# Generated by FakeRAM 2.0
VERSION 5.7 ;
BUSBITCHARS "[]" ;
PROPERTYDEFINITIONS
  MACRO width INTEGER ;
  MACRO depth INTEGER ;
  MACRO banks INTEGER ;
END PROPERTYDEFINITIONS
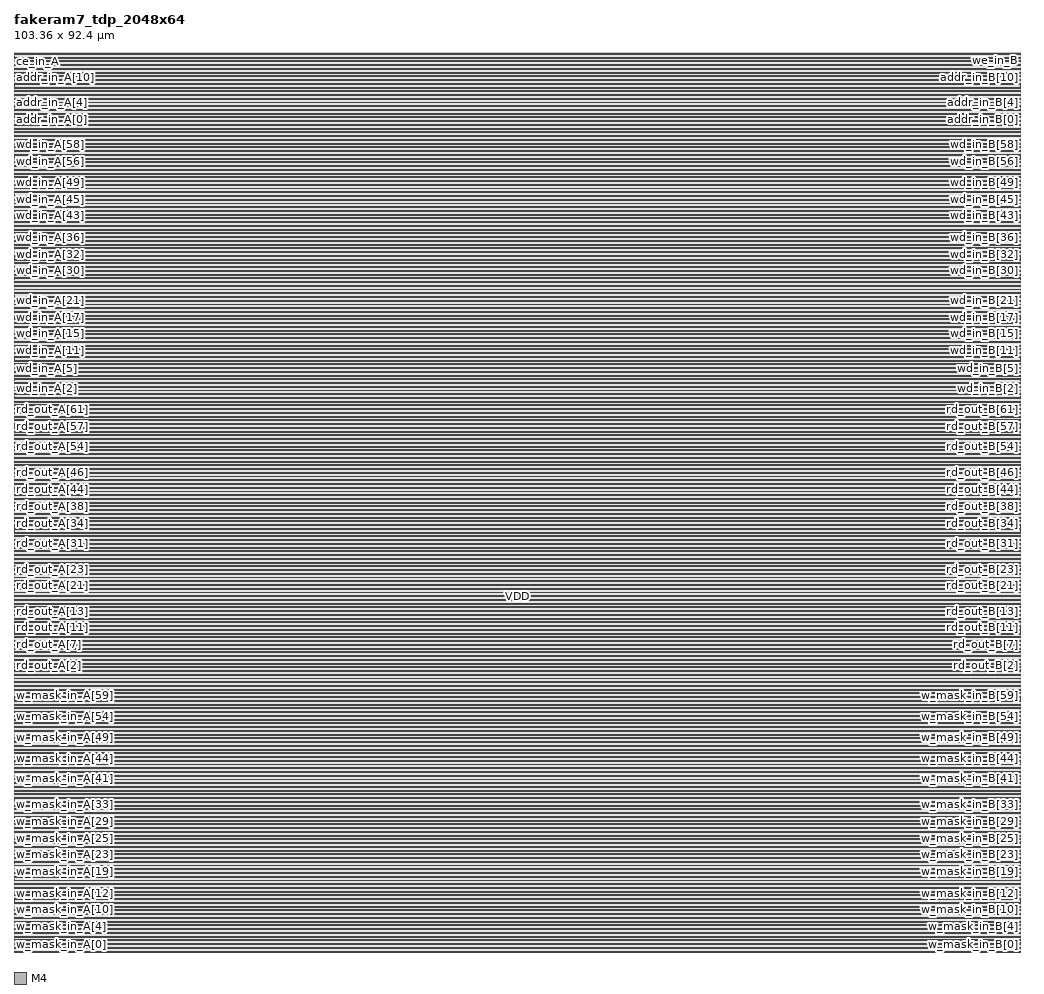
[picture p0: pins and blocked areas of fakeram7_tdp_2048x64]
MACRO fakeram7_tdp_2048x64
  PROPERTY width 64 ;
  PROPERTY depth 2048 ;
  PROPERTY banks 8 ;
  FOREIGN fakeram7_tdp_2048x64 0 0 ;
  SYMMETRY X Y ;
  SIZE 103.360 BY 92.400 ;
  CLASS BLOCK ;
  PIN w_mask_in_A[0]
    DIRECTION INPUT ;
    USE SIGNAL ;
    SHAPE ABUTMENT ;
    PORT
      LAYER M4 ;
      RECT 0.000 0.048 0.024 0.072 ;
    END
  END w_mask_in_A[0]
  PIN w_mask_in_B[0]
    DIRECTION INPUT ;
    USE SIGNAL ;
    SHAPE ABUTMENT ;
    PORT
      LAYER M4 ;
      RECT 103.336 0.048 103.360 0.072 ;
    END
  END w_mask_in_B[0]
  PIN w_mask_in_A[1]
    DIRECTION INPUT ;
    USE SIGNAL ;
    SHAPE ABUTMENT ;
    PORT
      LAYER M4 ;
      RECT 0.000 0.480 0.024 0.504 ;
    END
  END w_mask_in_A[1]
  PIN w_mask_in_B[1]
    DIRECTION INPUT ;
    USE SIGNAL ;
    SHAPE ABUTMENT ;
    PORT
      LAYER M4 ;
      RECT 103.336 0.480 103.360 0.504 ;
    END
  END w_mask_in_B[1]
  PIN w_mask_in_A[2]
    DIRECTION INPUT ;
    USE SIGNAL ;
    SHAPE ABUTMENT ;
    PORT
      LAYER M4 ;
      RECT 0.000 0.912 0.024 0.936 ;
    END
  END w_mask_in_A[2]
  PIN w_mask_in_B[2]
    DIRECTION INPUT ;
    USE SIGNAL ;
    SHAPE ABUTMENT ;
    PORT
      LAYER M4 ;
      RECT 103.336 0.912 103.360 0.936 ;
    END
  END w_mask_in_B[2]
  PIN w_mask_in_A[3]
    DIRECTION INPUT ;
    USE SIGNAL ;
    SHAPE ABUTMENT ;
    PORT
      LAYER M4 ;
      RECT 0.000 1.344 0.024 1.368 ;
    END
  END w_mask_in_A[3]
  PIN w_mask_in_B[3]
    DIRECTION INPUT ;
    USE SIGNAL ;
    SHAPE ABUTMENT ;
    PORT
      LAYER M4 ;
      RECT 103.336 1.344 103.360 1.368 ;
    END
  END w_mask_in_B[3]
  PIN w_mask_in_A[4]
    DIRECTION INPUT ;
    USE SIGNAL ;
    SHAPE ABUTMENT ;
    PORT
      LAYER M4 ;
      RECT 0.000 1.776 0.024 1.800 ;
    END
  END w_mask_in_A[4]
  PIN w_mask_in_B[4]
    DIRECTION INPUT ;
    USE SIGNAL ;
    SHAPE ABUTMENT ;
    PORT
      LAYER M4 ;
      RECT 103.336 1.776 103.360 1.800 ;
    END
  END w_mask_in_B[4]
  PIN w_mask_in_A[5]
    DIRECTION INPUT ;
    USE SIGNAL ;
    SHAPE ABUTMENT ;
    PORT
      LAYER M4 ;
      RECT 0.000 2.208 0.024 2.232 ;
    END
  END w_mask_in_A[5]
  PIN w_mask_in_B[5]
    DIRECTION INPUT ;
    USE SIGNAL ;
    SHAPE ABUTMENT ;
    PORT
      LAYER M4 ;
      RECT 103.336 2.208 103.360 2.232 ;
    END
  END w_mask_in_B[5]
  PIN w_mask_in_A[6]
    DIRECTION INPUT ;
    USE SIGNAL ;
    SHAPE ABUTMENT ;
    PORT
      LAYER M4 ;
      RECT 0.000 2.640 0.024 2.664 ;
    END
  END w_mask_in_A[6]
  PIN w_mask_in_B[6]
    DIRECTION INPUT ;
    USE SIGNAL ;
    SHAPE ABUTMENT ;
    PORT
      LAYER M4 ;
      RECT 103.336 2.640 103.360 2.664 ;
    END
  END w_mask_in_B[6]
  PIN w_mask_in_A[7]
    DIRECTION INPUT ;
    USE SIGNAL ;
    SHAPE ABUTMENT ;
    PORT
      LAYER M4 ;
      RECT 0.000 3.072 0.024 3.096 ;
    END
  END w_mask_in_A[7]
  PIN w_mask_in_B[7]
    DIRECTION INPUT ;
    USE SIGNAL ;
    SHAPE ABUTMENT ;
    PORT
      LAYER M4 ;
      RECT 103.336 3.072 103.360 3.096 ;
    END
  END w_mask_in_B[7]
  PIN w_mask_in_A[8]
    DIRECTION INPUT ;
    USE SIGNAL ;
    SHAPE ABUTMENT ;
    PORT
      LAYER M4 ;
      RECT 0.000 3.504 0.024 3.528 ;
    END
  END w_mask_in_A[8]
  PIN w_mask_in_B[8]
    DIRECTION INPUT ;
    USE SIGNAL ;
    SHAPE ABUTMENT ;
    PORT
      LAYER M4 ;
      RECT 103.336 3.504 103.360 3.528 ;
    END
  END w_mask_in_B[8]
  PIN w_mask_in_A[9]
    DIRECTION INPUT ;
    USE SIGNAL ;
    SHAPE ABUTMENT ;
    PORT
      LAYER M4 ;
      RECT 0.000 3.936 0.024 3.960 ;
    END
  END w_mask_in_A[9]
  PIN w_mask_in_B[9]
    DIRECTION INPUT ;
    USE SIGNAL ;
    SHAPE ABUTMENT ;
    PORT
      LAYER M4 ;
      RECT 103.336 3.936 103.360 3.960 ;
    END
  END w_mask_in_B[9]
  PIN w_mask_in_A[10]
    DIRECTION INPUT ;
    USE SIGNAL ;
    SHAPE ABUTMENT ;
    PORT
      LAYER M4 ;
      RECT 0.000 4.368 0.024 4.392 ;
    END
  END w_mask_in_A[10]
  PIN w_mask_in_B[10]
    DIRECTION INPUT ;
    USE SIGNAL ;
    SHAPE ABUTMENT ;
    PORT
      LAYER M4 ;
      RECT 103.336 4.368 103.360 4.392 ;
    END
  END w_mask_in_B[10]
  PIN w_mask_in_A[11]
    DIRECTION INPUT ;
    USE SIGNAL ;
    SHAPE ABUTMENT ;
    PORT
      LAYER M4 ;
      RECT 0.000 4.800 0.024 4.824 ;
    END
  END w_mask_in_A[11]
  PIN w_mask_in_B[11]
    DIRECTION INPUT ;
    USE SIGNAL ;
    SHAPE ABUTMENT ;
    PORT
      LAYER M4 ;
      RECT 103.336 4.800 103.360 4.824 ;
    END
  END w_mask_in_B[11]
  PIN w_mask_in_A[12]
    DIRECTION INPUT ;
    USE SIGNAL ;
    SHAPE ABUTMENT ;
    PORT
      LAYER M4 ;
      RECT 0.000 5.232 0.024 5.256 ;
    END
  END w_mask_in_A[12]
  PIN w_mask_in_B[12]
    DIRECTION INPUT ;
    USE SIGNAL ;
    SHAPE ABUTMENT ;
    PORT
      LAYER M4 ;
      RECT 103.336 5.232 103.360 5.256 ;
    END
  END w_mask_in_B[12]
  PIN w_mask_in_A[13]
    DIRECTION INPUT ;
    USE SIGNAL ;
    SHAPE ABUTMENT ;
    PORT
      LAYER M4 ;
      RECT 0.000 5.664 0.024 5.688 ;
    END
  END w_mask_in_A[13]
  PIN w_mask_in_B[13]
    DIRECTION INPUT ;
    USE SIGNAL ;
    SHAPE ABUTMENT ;
    PORT
      LAYER M4 ;
      RECT 103.336 5.664 103.360 5.688 ;
    END
  END w_mask_in_B[13]
  PIN w_mask_in_A[14]
    DIRECTION INPUT ;
    USE SIGNAL ;
    SHAPE ABUTMENT ;
    PORT
      LAYER M4 ;
      RECT 0.000 6.096 0.024 6.120 ;
    END
  END w_mask_in_A[14]
  PIN w_mask_in_B[14]
    DIRECTION INPUT ;
    USE SIGNAL ;
    SHAPE ABUTMENT ;
    PORT
      LAYER M4 ;
      RECT 103.336 6.096 103.360 6.120 ;
    END
  END w_mask_in_B[14]
  PIN w_mask_in_A[15]
    DIRECTION INPUT ;
    USE SIGNAL ;
    SHAPE ABUTMENT ;
    PORT
      LAYER M4 ;
      RECT 0.000 6.528 0.024 6.552 ;
    END
  END w_mask_in_A[15]
  PIN w_mask_in_B[15]
    DIRECTION INPUT ;
    USE SIGNAL ;
    SHAPE ABUTMENT ;
    PORT
      LAYER M4 ;
      RECT 103.336 6.528 103.360 6.552 ;
    END
  END w_mask_in_B[15]
  PIN w_mask_in_A[16]
    DIRECTION INPUT ;
    USE SIGNAL ;
    SHAPE ABUTMENT ;
    PORT
      LAYER M4 ;
      RECT 0.000 6.960 0.024 6.984 ;
    END
  END w_mask_in_A[16]
  PIN w_mask_in_B[16]
    DIRECTION INPUT ;
    USE SIGNAL ;
    SHAPE ABUTMENT ;
    PORT
      LAYER M4 ;
      RECT 103.336 6.960 103.360 6.984 ;
    END
  END w_mask_in_B[16]
  PIN w_mask_in_A[17]
    DIRECTION INPUT ;
    USE SIGNAL ;
    SHAPE ABUTMENT ;
    PORT
      LAYER M4 ;
      RECT 0.000 7.392 0.024 7.416 ;
    END
  END w_mask_in_A[17]
  PIN w_mask_in_B[17]
    DIRECTION INPUT ;
    USE SIGNAL ;
    SHAPE ABUTMENT ;
    PORT
      LAYER M4 ;
      RECT 103.336 7.392 103.360 7.416 ;
    END
  END w_mask_in_B[17]
  PIN w_mask_in_A[18]
    DIRECTION INPUT ;
    USE SIGNAL ;
    SHAPE ABUTMENT ;
    PORT
      LAYER M4 ;
      RECT 0.000 7.824 0.024 7.848 ;
    END
  END w_mask_in_A[18]
  PIN w_mask_in_B[18]
    DIRECTION INPUT ;
    USE SIGNAL ;
    SHAPE ABUTMENT ;
    PORT
      LAYER M4 ;
      RECT 103.336 7.824 103.360 7.848 ;
    END
  END w_mask_in_B[18]
  PIN w_mask_in_A[19]
    DIRECTION INPUT ;
    USE SIGNAL ;
    SHAPE ABUTMENT ;
    PORT
      LAYER M4 ;
      RECT 0.000 8.256 0.024 8.280 ;
    END
  END w_mask_in_A[19]
  PIN w_mask_in_B[19]
    DIRECTION INPUT ;
    USE SIGNAL ;
    SHAPE ABUTMENT ;
    PORT
      LAYER M4 ;
      RECT 103.336 8.256 103.360 8.280 ;
    END
  END w_mask_in_B[19]
  PIN w_mask_in_A[20]
    DIRECTION INPUT ;
    USE SIGNAL ;
    SHAPE ABUTMENT ;
    PORT
      LAYER M4 ;
      RECT 0.000 8.688 0.024 8.712 ;
    END
  END w_mask_in_A[20]
  PIN w_mask_in_B[20]
    DIRECTION INPUT ;
    USE SIGNAL ;
    SHAPE ABUTMENT ;
    PORT
      LAYER M4 ;
      RECT 103.336 8.688 103.360 8.712 ;
    END
  END w_mask_in_B[20]
  PIN w_mask_in_A[21]
    DIRECTION INPUT ;
    USE SIGNAL ;
    SHAPE ABUTMENT ;
    PORT
      LAYER M4 ;
      RECT 0.000 9.120 0.024 9.144 ;
    END
  END w_mask_in_A[21]
  PIN w_mask_in_B[21]
    DIRECTION INPUT ;
    USE SIGNAL ;
    SHAPE ABUTMENT ;
    PORT
      LAYER M4 ;
      RECT 103.336 9.120 103.360 9.144 ;
    END
  END w_mask_in_B[21]
  PIN w_mask_in_A[22]
    DIRECTION INPUT ;
    USE SIGNAL ;
    SHAPE ABUTMENT ;
    PORT
      LAYER M4 ;
      RECT 0.000 9.552 0.024 9.576 ;
    END
  END w_mask_in_A[22]
  PIN w_mask_in_B[22]
    DIRECTION INPUT ;
    USE SIGNAL ;
    SHAPE ABUTMENT ;
    PORT
      LAYER M4 ;
      RECT 103.336 9.552 103.360 9.576 ;
    END
  END w_mask_in_B[22]
  PIN w_mask_in_A[23]
    DIRECTION INPUT ;
    USE SIGNAL ;
    SHAPE ABUTMENT ;
    PORT
      LAYER M4 ;
      RECT 0.000 9.984 0.024 10.008 ;
    END
  END w_mask_in_A[23]
  PIN w_mask_in_B[23]
    DIRECTION INPUT ;
    USE SIGNAL ;
    SHAPE ABUTMENT ;
    PORT
      LAYER M4 ;
      RECT 103.336 9.984 103.360 10.008 ;
    END
  END w_mask_in_B[23]
  PIN w_mask_in_A[24]
    DIRECTION INPUT ;
    USE SIGNAL ;
    SHAPE ABUTMENT ;
    PORT
      LAYER M4 ;
      RECT 0.000 10.416 0.024 10.440 ;
    END
  END w_mask_in_A[24]
  PIN w_mask_in_B[24]
    DIRECTION INPUT ;
    USE SIGNAL ;
    SHAPE ABUTMENT ;
    PORT
      LAYER M4 ;
      RECT 103.336 10.416 103.360 10.440 ;
    END
  END w_mask_in_B[24]
  PIN w_mask_in_A[25]
    DIRECTION INPUT ;
    USE SIGNAL ;
    SHAPE ABUTMENT ;
    PORT
      LAYER M4 ;
      RECT 0.000 10.848 0.024 10.872 ;
    END
  END w_mask_in_A[25]
  PIN w_mask_in_B[25]
    DIRECTION INPUT ;
    USE SIGNAL ;
    SHAPE ABUTMENT ;
    PORT
      LAYER M4 ;
      RECT 103.336 10.848 103.360 10.872 ;
    END
  END w_mask_in_B[25]
  PIN w_mask_in_A[26]
    DIRECTION INPUT ;
    USE SIGNAL ;
    SHAPE ABUTMENT ;
    PORT
      LAYER M4 ;
      RECT 0.000 11.280 0.024 11.304 ;
    END
  END w_mask_in_A[26]
  PIN w_mask_in_B[26]
    DIRECTION INPUT ;
    USE SIGNAL ;
    SHAPE ABUTMENT ;
    PORT
      LAYER M4 ;
      RECT 103.336 11.280 103.360 11.304 ;
    END
  END w_mask_in_B[26]
  PIN w_mask_in_A[27]
    DIRECTION INPUT ;
    USE SIGNAL ;
    SHAPE ABUTMENT ;
    PORT
      LAYER M4 ;
      RECT 0.000 11.712 0.024 11.736 ;
    END
  END w_mask_in_A[27]
  PIN w_mask_in_B[27]
    DIRECTION INPUT ;
    USE SIGNAL ;
    SHAPE ABUTMENT ;
    PORT
      LAYER M4 ;
      RECT 103.336 11.712 103.360 11.736 ;
    END
  END w_mask_in_B[27]
  PIN w_mask_in_A[28]
    DIRECTION INPUT ;
    USE SIGNAL ;
    SHAPE ABUTMENT ;
    PORT
      LAYER M4 ;
      RECT 0.000 12.144 0.024 12.168 ;
    END
  END w_mask_in_A[28]
  PIN w_mask_in_B[28]
    DIRECTION INPUT ;
    USE SIGNAL ;
    SHAPE ABUTMENT ;
    PORT
      LAYER M4 ;
      RECT 103.336 12.144 103.360 12.168 ;
    END
  END w_mask_in_B[28]
  PIN w_mask_in_A[29]
    DIRECTION INPUT ;
    USE SIGNAL ;
    SHAPE ABUTMENT ;
    PORT
      LAYER M4 ;
      RECT 0.000 12.576 0.024 12.600 ;
    END
  END w_mask_in_A[29]
  PIN w_mask_in_B[29]
    DIRECTION INPUT ;
    USE SIGNAL ;
    SHAPE ABUTMENT ;
    PORT
      LAYER M4 ;
      RECT 103.336 12.576 103.360 12.600 ;
    END
  END w_mask_in_B[29]
  PIN w_mask_in_A[30]
    DIRECTION INPUT ;
    USE SIGNAL ;
    SHAPE ABUTMENT ;
    PORT
      LAYER M4 ;
      RECT 0.000 13.008 0.024 13.032 ;
    END
  END w_mask_in_A[30]
  PIN w_mask_in_B[30]
    DIRECTION INPUT ;
    USE SIGNAL ;
    SHAPE ABUTMENT ;
    PORT
      LAYER M4 ;
      RECT 103.336 13.008 103.360 13.032 ;
    END
  END w_mask_in_B[30]
  PIN w_mask_in_A[31]
    DIRECTION INPUT ;
    USE SIGNAL ;
    SHAPE ABUTMENT ;
    PORT
      LAYER M4 ;
      RECT 0.000 13.440 0.024 13.464 ;
    END
  END w_mask_in_A[31]
  PIN w_mask_in_B[31]
    DIRECTION INPUT ;
    USE SIGNAL ;
    SHAPE ABUTMENT ;
    PORT
      LAYER M4 ;
      RECT 103.336 13.440 103.360 13.464 ;
    END
  END w_mask_in_B[31]
  PIN w_mask_in_A[32]
    DIRECTION INPUT ;
    USE SIGNAL ;
    SHAPE ABUTMENT ;
    PORT
      LAYER M4 ;
      RECT 0.000 13.872 0.024 13.896 ;
    END
  END w_mask_in_A[32]
  PIN w_mask_in_B[32]
    DIRECTION INPUT ;
    USE SIGNAL ;
    SHAPE ABUTMENT ;
    PORT
      LAYER M4 ;
      RECT 103.336 13.872 103.360 13.896 ;
    END
  END w_mask_in_B[32]
  PIN w_mask_in_A[33]
    DIRECTION INPUT ;
    USE SIGNAL ;
    SHAPE ABUTMENT ;
    PORT
      LAYER M4 ;
      RECT 0.000 14.304 0.024 14.328 ;
    END
  END w_mask_in_A[33]
  PIN w_mask_in_B[33]
    DIRECTION INPUT ;
    USE SIGNAL ;
    SHAPE ABUTMENT ;
    PORT
      LAYER M4 ;
      RECT 103.336 14.304 103.360 14.328 ;
    END
  END w_mask_in_B[33]
  PIN w_mask_in_A[34]
    DIRECTION INPUT ;
    USE SIGNAL ;
    SHAPE ABUTMENT ;
    PORT
      LAYER M4 ;
      RECT 0.000 14.736 0.024 14.760 ;
    END
  END w_mask_in_A[34]
  PIN w_mask_in_B[34]
    DIRECTION INPUT ;
    USE SIGNAL ;
    SHAPE ABUTMENT ;
    PORT
      LAYER M4 ;
      RECT 103.336 14.736 103.360 14.760 ;
    END
  END w_mask_in_B[34]
  PIN w_mask_in_A[35]
    DIRECTION INPUT ;
    USE SIGNAL ;
    SHAPE ABUTMENT ;
    PORT
      LAYER M4 ;
      RECT 0.000 15.168 0.024 15.192 ;
    END
  END w_mask_in_A[35]
  PIN w_mask_in_B[35]
    DIRECTION INPUT ;
    USE SIGNAL ;
    SHAPE ABUTMENT ;
    PORT
      LAYER M4 ;
      RECT 103.336 15.168 103.360 15.192 ;
    END
  END w_mask_in_B[35]
  PIN w_mask_in_A[36]
    DIRECTION INPUT ;
    USE SIGNAL ;
    SHAPE ABUTMENT ;
    PORT
      LAYER M4 ;
      RECT 0.000 15.600 0.024 15.624 ;
    END
  END w_mask_in_A[36]
  PIN w_mask_in_B[36]
    DIRECTION INPUT ;
    USE SIGNAL ;
    SHAPE ABUTMENT ;
    PORT
      LAYER M4 ;
      RECT 103.336 15.600 103.360 15.624 ;
    END
  END w_mask_in_B[36]
  PIN w_mask_in_A[37]
    DIRECTION INPUT ;
    USE SIGNAL ;
    SHAPE ABUTMENT ;
    PORT
      LAYER M4 ;
      RECT 0.000 16.032 0.024 16.056 ;
    END
  END w_mask_in_A[37]
  PIN w_mask_in_B[37]
    DIRECTION INPUT ;
    USE SIGNAL ;
    SHAPE ABUTMENT ;
    PORT
      LAYER M4 ;
      RECT 103.336 16.032 103.360 16.056 ;
    END
  END w_mask_in_B[37]
  PIN w_mask_in_A[38]
    DIRECTION INPUT ;
    USE SIGNAL ;
    SHAPE ABUTMENT ;
    PORT
      LAYER M4 ;
      RECT 0.000 16.464 0.024 16.488 ;
    END
  END w_mask_in_A[38]
  PIN w_mask_in_B[38]
    DIRECTION INPUT ;
    USE SIGNAL ;
    SHAPE ABUTMENT ;
    PORT
      LAYER M4 ;
      RECT 103.336 16.464 103.360 16.488 ;
    END
  END w_mask_in_B[38]
  PIN w_mask_in_A[39]
    DIRECTION INPUT ;
    USE SIGNAL ;
    SHAPE ABUTMENT ;
    PORT
      LAYER M4 ;
      RECT 0.000 16.896 0.024 16.920 ;
    END
  END w_mask_in_A[39]
  PIN w_mask_in_B[39]
    DIRECTION INPUT ;
    USE SIGNAL ;
    SHAPE ABUTMENT ;
    PORT
      LAYER M4 ;
      RECT 103.336 16.896 103.360 16.920 ;
    END
  END w_mask_in_B[39]
  PIN w_mask_in_A[40]
    DIRECTION INPUT ;
    USE SIGNAL ;
    SHAPE ABUTMENT ;
    PORT
      LAYER M4 ;
      RECT 0.000 17.328 0.024 17.352 ;
    END
  END w_mask_in_A[40]
  PIN w_mask_in_B[40]
    DIRECTION INPUT ;
    USE SIGNAL ;
    SHAPE ABUTMENT ;
    PORT
      LAYER M4 ;
      RECT 103.336 17.328 103.360 17.352 ;
    END
  END w_mask_in_B[40]
  PIN w_mask_in_A[41]
    DIRECTION INPUT ;
    USE SIGNAL ;
    SHAPE ABUTMENT ;
    PORT
      LAYER M4 ;
      RECT 0.000 17.760 0.024 17.784 ;
    END
  END w_mask_in_A[41]
  PIN w_mask_in_B[41]
    DIRECTION INPUT ;
    USE SIGNAL ;
    SHAPE ABUTMENT ;
    PORT
      LAYER M4 ;
      RECT 103.336 17.760 103.360 17.784 ;
    END
  END w_mask_in_B[41]
  PIN w_mask_in_A[42]
    DIRECTION INPUT ;
    USE SIGNAL ;
    SHAPE ABUTMENT ;
    PORT
      LAYER M4 ;
      RECT 0.000 18.192 0.024 18.216 ;
    END
  END w_mask_in_A[42]
  PIN w_mask_in_B[42]
    DIRECTION INPUT ;
    USE SIGNAL ;
    SHAPE ABUTMENT ;
    PORT
      LAYER M4 ;
      RECT 103.336 18.192 103.360 18.216 ;
    END
  END w_mask_in_B[42]
  PIN w_mask_in_A[43]
    DIRECTION INPUT ;
    USE SIGNAL ;
    SHAPE ABUTMENT ;
    PORT
      LAYER M4 ;
      RECT 0.000 18.624 0.024 18.648 ;
    END
  END w_mask_in_A[43]
  PIN w_mask_in_B[43]
    DIRECTION INPUT ;
    USE SIGNAL ;
    SHAPE ABUTMENT ;
    PORT
      LAYER M4 ;
      RECT 103.336 18.624 103.360 18.648 ;
    END
  END w_mask_in_B[43]
  PIN w_mask_in_A[44]
    DIRECTION INPUT ;
    USE SIGNAL ;
    SHAPE ABUTMENT ;
    PORT
      LAYER M4 ;
      RECT 0.000 19.056 0.024 19.080 ;
    END
  END w_mask_in_A[44]
  PIN w_mask_in_B[44]
    DIRECTION INPUT ;
    USE SIGNAL ;
    SHAPE ABUTMENT ;
    PORT
      LAYER M4 ;
      RECT 103.336 19.056 103.360 19.080 ;
    END
  END w_mask_in_B[44]
  PIN w_mask_in_A[45]
    DIRECTION INPUT ;
    USE SIGNAL ;
    SHAPE ABUTMENT ;
    PORT
      LAYER M4 ;
      RECT 0.000 19.488 0.024 19.512 ;
    END
  END w_mask_in_A[45]
  PIN w_mask_in_B[45]
    DIRECTION INPUT ;
    USE SIGNAL ;
    SHAPE ABUTMENT ;
    PORT
      LAYER M4 ;
      RECT 103.336 19.488 103.360 19.512 ;
    END
  END w_mask_in_B[45]
  PIN w_mask_in_A[46]
    DIRECTION INPUT ;
    USE SIGNAL ;
    SHAPE ABUTMENT ;
    PORT
      LAYER M4 ;
      RECT 0.000 19.920 0.024 19.944 ;
    END
  END w_mask_in_A[46]
  PIN w_mask_in_B[46]
    DIRECTION INPUT ;
    USE SIGNAL ;
    SHAPE ABUTMENT ;
    PORT
      LAYER M4 ;
      RECT 103.336 19.920 103.360 19.944 ;
    END
  END w_mask_in_B[46]
  PIN w_mask_in_A[47]
    DIRECTION INPUT ;
    USE SIGNAL ;
    SHAPE ABUTMENT ;
    PORT
      LAYER M4 ;
      RECT 0.000 20.352 0.024 20.376 ;
    END
  END w_mask_in_A[47]
  PIN w_mask_in_B[47]
    DIRECTION INPUT ;
    USE SIGNAL ;
    SHAPE ABUTMENT ;
    PORT
      LAYER M4 ;
      RECT 103.336 20.352 103.360 20.376 ;
    END
  END w_mask_in_B[47]
  PIN w_mask_in_A[48]
    DIRECTION INPUT ;
    USE SIGNAL ;
    SHAPE ABUTMENT ;
    PORT
      LAYER M4 ;
      RECT 0.000 20.784 0.024 20.808 ;
    END
  END w_mask_in_A[48]
  PIN w_mask_in_B[48]
    DIRECTION INPUT ;
    USE SIGNAL ;
    SHAPE ABUTMENT ;
    PORT
      LAYER M4 ;
      RECT 103.336 20.784 103.360 20.808 ;
    END
  END w_mask_in_B[48]
  PIN w_mask_in_A[49]
    DIRECTION INPUT ;
    USE SIGNAL ;
    SHAPE ABUTMENT ;
    PORT
      LAYER M4 ;
      RECT 0.000 21.216 0.024 21.240 ;
    END
  END w_mask_in_A[49]
  PIN w_mask_in_B[49]
    DIRECTION INPUT ;
    USE SIGNAL ;
    SHAPE ABUTMENT ;
    PORT
      LAYER M4 ;
      RECT 103.336 21.216 103.360 21.240 ;
    END
  END w_mask_in_B[49]
  PIN w_mask_in_A[50]
    DIRECTION INPUT ;
    USE SIGNAL ;
    SHAPE ABUTMENT ;
    PORT
      LAYER M4 ;
      RECT 0.000 21.648 0.024 21.672 ;
    END
  END w_mask_in_A[50]
  PIN w_mask_in_B[50]
    DIRECTION INPUT ;
    USE SIGNAL ;
    SHAPE ABUTMENT ;
    PORT
      LAYER M4 ;
      RECT 103.336 21.648 103.360 21.672 ;
    END
  END w_mask_in_B[50]
  PIN w_mask_in_A[51]
    DIRECTION INPUT ;
    USE SIGNAL ;
    SHAPE ABUTMENT ;
    PORT
      LAYER M4 ;
      RECT 0.000 22.080 0.024 22.104 ;
    END
  END w_mask_in_A[51]
  PIN w_mask_in_B[51]
    DIRECTION INPUT ;
    USE SIGNAL ;
    SHAPE ABUTMENT ;
    PORT
      LAYER M4 ;
      RECT 103.336 22.080 103.360 22.104 ;
    END
  END w_mask_in_B[51]
  PIN w_mask_in_A[52]
    DIRECTION INPUT ;
    USE SIGNAL ;
    SHAPE ABUTMENT ;
    PORT
      LAYER M4 ;
      RECT 0.000 22.512 0.024 22.536 ;
    END
  END w_mask_in_A[52]
  PIN w_mask_in_B[52]
    DIRECTION INPUT ;
    USE SIGNAL ;
    SHAPE ABUTMENT ;
    PORT
      LAYER M4 ;
      RECT 103.336 22.512 103.360 22.536 ;
    END
  END w_mask_in_B[52]
  PIN w_mask_in_A[53]
    DIRECTION INPUT ;
    USE SIGNAL ;
    SHAPE ABUTMENT ;
    PORT
      LAYER M4 ;
      RECT 0.000 22.944 0.024 22.968 ;
    END
  END w_mask_in_A[53]
  PIN w_mask_in_B[53]
    DIRECTION INPUT ;
    USE SIGNAL ;
    SHAPE ABUTMENT ;
    PORT
      LAYER M4 ;
      RECT 103.336 22.944 103.360 22.968 ;
    END
  END w_mask_in_B[53]
  PIN w_mask_in_A[54]
    DIRECTION INPUT ;
    USE SIGNAL ;
    SHAPE ABUTMENT ;
    PORT
      LAYER M4 ;
      RECT 0.000 23.376 0.024 23.400 ;
    END
  END w_mask_in_A[54]
  PIN w_mask_in_B[54]
    DIRECTION INPUT ;
    USE SIGNAL ;
    SHAPE ABUTMENT ;
    PORT
      LAYER M4 ;
      RECT 103.336 23.376 103.360 23.400 ;
    END
  END w_mask_in_B[54]
  PIN w_mask_in_A[55]
    DIRECTION INPUT ;
    USE SIGNAL ;
    SHAPE ABUTMENT ;
    PORT
      LAYER M4 ;
      RECT 0.000 23.808 0.024 23.832 ;
    END
  END w_mask_in_A[55]
  PIN w_mask_in_B[55]
    DIRECTION INPUT ;
    USE SIGNAL ;
    SHAPE ABUTMENT ;
    PORT
      LAYER M4 ;
      RECT 103.336 23.808 103.360 23.832 ;
    END
  END w_mask_in_B[55]
  PIN w_mask_in_A[56]
    DIRECTION INPUT ;
    USE SIGNAL ;
    SHAPE ABUTMENT ;
    PORT
      LAYER M4 ;
      RECT 0.000 24.240 0.024 24.264 ;
    END
  END w_mask_in_A[56]
  PIN w_mask_in_B[56]
    DIRECTION INPUT ;
    USE SIGNAL ;
    SHAPE ABUTMENT ;
    PORT
      LAYER M4 ;
      RECT 103.336 24.240 103.360 24.264 ;
    END
  END w_mask_in_B[56]
  PIN w_mask_in_A[57]
    DIRECTION INPUT ;
    USE SIGNAL ;
    SHAPE ABUTMENT ;
    PORT
      LAYER M4 ;
      RECT 0.000 24.672 0.024 24.696 ;
    END
  END w_mask_in_A[57]
  PIN w_mask_in_B[57]
    DIRECTION INPUT ;
    USE SIGNAL ;
    SHAPE ABUTMENT ;
    PORT
      LAYER M4 ;
      RECT 103.336 24.672 103.360 24.696 ;
    END
  END w_mask_in_B[57]
  PIN w_mask_in_A[58]
    DIRECTION INPUT ;
    USE SIGNAL ;
    SHAPE ABUTMENT ;
    PORT
      LAYER M4 ;
      RECT 0.000 25.104 0.024 25.128 ;
    END
  END w_mask_in_A[58]
  PIN w_mask_in_B[58]
    DIRECTION INPUT ;
    USE SIGNAL ;
    SHAPE ABUTMENT ;
    PORT
      LAYER M4 ;
      RECT 103.336 25.104 103.360 25.128 ;
    END
  END w_mask_in_B[58]
  PIN w_mask_in_A[59]
    DIRECTION INPUT ;
    USE SIGNAL ;
    SHAPE ABUTMENT ;
    PORT
      LAYER M4 ;
      RECT 0.000 25.536 0.024 25.560 ;
    END
  END w_mask_in_A[59]
  PIN w_mask_in_B[59]
    DIRECTION INPUT ;
    USE SIGNAL ;
    SHAPE ABUTMENT ;
    PORT
      LAYER M4 ;
      RECT 103.336 25.536 103.360 25.560 ;
    END
  END w_mask_in_B[59]
  PIN w_mask_in_A[60]
    DIRECTION INPUT ;
    USE SIGNAL ;
    SHAPE ABUTMENT ;
    PORT
      LAYER M4 ;
      RECT 0.000 25.968 0.024 25.992 ;
    END
  END w_mask_in_A[60]
  PIN w_mask_in_B[60]
    DIRECTION INPUT ;
    USE SIGNAL ;
    SHAPE ABUTMENT ;
    PORT
      LAYER M4 ;
      RECT 103.336 25.968 103.360 25.992 ;
    END
  END w_mask_in_B[60]
  PIN w_mask_in_A[61]
    DIRECTION INPUT ;
    USE SIGNAL ;
    SHAPE ABUTMENT ;
    PORT
      LAYER M4 ;
      RECT 0.000 26.400 0.024 26.424 ;
    END
  END w_mask_in_A[61]
  PIN w_mask_in_B[61]
    DIRECTION INPUT ;
    USE SIGNAL ;
    SHAPE ABUTMENT ;
    PORT
      LAYER M4 ;
      RECT 103.336 26.400 103.360 26.424 ;
    END
  END w_mask_in_B[61]
  PIN w_mask_in_A[62]
    DIRECTION INPUT ;
    USE SIGNAL ;
    SHAPE ABUTMENT ;
    PORT
      LAYER M4 ;
      RECT 0.000 26.832 0.024 26.856 ;
    END
  END w_mask_in_A[62]
  PIN w_mask_in_B[62]
    DIRECTION INPUT ;
    USE SIGNAL ;
    SHAPE ABUTMENT ;
    PORT
      LAYER M4 ;
      RECT 103.336 26.832 103.360 26.856 ;
    END
  END w_mask_in_B[62]
  PIN w_mask_in_A[63]
    DIRECTION INPUT ;
    USE SIGNAL ;
    SHAPE ABUTMENT ;
    PORT
      LAYER M4 ;
      RECT 0.000 27.264 0.024 27.288 ;
    END
  END w_mask_in_A[63]
  PIN w_mask_in_B[63]
    DIRECTION INPUT ;
    USE SIGNAL ;
    SHAPE ABUTMENT ;
    PORT
      LAYER M4 ;
      RECT 103.336 27.264 103.360 27.288 ;
    END
  END w_mask_in_B[63]
  PIN rd_out_A[0]
    DIRECTION OUTPUT ;
    USE SIGNAL ;
    SHAPE ABUTMENT ;
    PORT
      LAYER M4 ;
      RECT 0.000 28.512 0.024 28.536 ;
    END
  END rd_out_A[0]
  PIN rd_out_B[0]
    DIRECTION OUTPUT ;
    USE SIGNAL ;
    SHAPE ABUTMENT ;
    PORT
      LAYER M4 ;
      RECT 103.336 28.512 103.360 28.536 ;
    END
  END rd_out_B[0]
  PIN rd_out_A[1]
    DIRECTION OUTPUT ;
    USE SIGNAL ;
    SHAPE ABUTMENT ;
    PORT
      LAYER M4 ;
      RECT 0.000 28.944 0.024 28.968 ;
    END
  END rd_out_A[1]
  PIN rd_out_B[1]
    DIRECTION OUTPUT ;
    USE SIGNAL ;
    SHAPE ABUTMENT ;
    PORT
      LAYER M4 ;
      RECT 103.336 28.944 103.360 28.968 ;
    END
  END rd_out_B[1]
  PIN rd_out_A[2]
    DIRECTION OUTPUT ;
    USE SIGNAL ;
    SHAPE ABUTMENT ;
    PORT
      LAYER M4 ;
      RECT 0.000 29.376 0.024 29.400 ;
    END
  END rd_out_A[2]
  PIN rd_out_B[2]
    DIRECTION OUTPUT ;
    USE SIGNAL ;
    SHAPE ABUTMENT ;
    PORT
      LAYER M4 ;
      RECT 103.336 29.376 103.360 29.400 ;
    END
  END rd_out_B[2]
  PIN rd_out_A[3]
    DIRECTION OUTPUT ;
    USE SIGNAL ;
    SHAPE ABUTMENT ;
    PORT
      LAYER M4 ;
      RECT 0.000 29.808 0.024 29.832 ;
    END
  END rd_out_A[3]
  PIN rd_out_B[3]
    DIRECTION OUTPUT ;
    USE SIGNAL ;
    SHAPE ABUTMENT ;
    PORT
      LAYER M4 ;
      RECT 103.336 29.808 103.360 29.832 ;
    END
  END rd_out_B[3]
  PIN rd_out_A[4]
    DIRECTION OUTPUT ;
    USE SIGNAL ;
    SHAPE ABUTMENT ;
    PORT
      LAYER M4 ;
      RECT 0.000 30.240 0.024 30.264 ;
    END
  END rd_out_A[4]
  PIN rd_out_B[4]
    DIRECTION OUTPUT ;
    USE SIGNAL ;
    SHAPE ABUTMENT ;
    PORT
      LAYER M4 ;
      RECT 103.336 30.240 103.360 30.264 ;
    END
  END rd_out_B[4]
  PIN rd_out_A[5]
    DIRECTION OUTPUT ;
    USE SIGNAL ;
    SHAPE ABUTMENT ;
    PORT
      LAYER M4 ;
      RECT 0.000 30.672 0.024 30.696 ;
    END
  END rd_out_A[5]
  PIN rd_out_B[5]
    DIRECTION OUTPUT ;
    USE SIGNAL ;
    SHAPE ABUTMENT ;
    PORT
      LAYER M4 ;
      RECT 103.336 30.672 103.360 30.696 ;
    END
  END rd_out_B[5]
  PIN rd_out_A[6]
    DIRECTION OUTPUT ;
    USE SIGNAL ;
    SHAPE ABUTMENT ;
    PORT
      LAYER M4 ;
      RECT 0.000 31.104 0.024 31.128 ;
    END
  END rd_out_A[6]
  PIN rd_out_B[6]
    DIRECTION OUTPUT ;
    USE SIGNAL ;
    SHAPE ABUTMENT ;
    PORT
      LAYER M4 ;
      RECT 103.336 31.104 103.360 31.128 ;
    END
  END rd_out_B[6]
  PIN rd_out_A[7]
    DIRECTION OUTPUT ;
    USE SIGNAL ;
    SHAPE ABUTMENT ;
    PORT
      LAYER M4 ;
      RECT 0.000 31.536 0.024 31.560 ;
    END
  END rd_out_A[7]
  PIN rd_out_B[7]
    DIRECTION OUTPUT ;
    USE SIGNAL ;
    SHAPE ABUTMENT ;
    PORT
      LAYER M4 ;
      RECT 103.336 31.536 103.360 31.560 ;
    END
  END rd_out_B[7]
  PIN rd_out_A[8]
    DIRECTION OUTPUT ;
    USE SIGNAL ;
    SHAPE ABUTMENT ;
    PORT
      LAYER M4 ;
      RECT 0.000 31.968 0.024 31.992 ;
    END
  END rd_out_A[8]
  PIN rd_out_B[8]
    DIRECTION OUTPUT ;
    USE SIGNAL ;
    SHAPE ABUTMENT ;
    PORT
      LAYER M4 ;
      RECT 103.336 31.968 103.360 31.992 ;
    END
  END rd_out_B[8]
  PIN rd_out_A[9]
    DIRECTION OUTPUT ;
    USE SIGNAL ;
    SHAPE ABUTMENT ;
    PORT
      LAYER M4 ;
      RECT 0.000 32.400 0.024 32.424 ;
    END
  END rd_out_A[9]
  PIN rd_out_B[9]
    DIRECTION OUTPUT ;
    USE SIGNAL ;
    SHAPE ABUTMENT ;
    PORT
      LAYER M4 ;
      RECT 103.336 32.400 103.360 32.424 ;
    END
  END rd_out_B[9]
  PIN rd_out_A[10]
    DIRECTION OUTPUT ;
    USE SIGNAL ;
    SHAPE ABUTMENT ;
    PORT
      LAYER M4 ;
      RECT 0.000 32.832 0.024 32.856 ;
    END
  END rd_out_A[10]
  PIN rd_out_B[10]
    DIRECTION OUTPUT ;
    USE SIGNAL ;
    SHAPE ABUTMENT ;
    PORT
      LAYER M4 ;
      RECT 103.336 32.832 103.360 32.856 ;
    END
  END rd_out_B[10]
  PIN rd_out_A[11]
    DIRECTION OUTPUT ;
    USE SIGNAL ;
    SHAPE ABUTMENT ;
    PORT
      LAYER M4 ;
      RECT 0.000 33.264 0.024 33.288 ;
    END
  END rd_out_A[11]
  PIN rd_out_B[11]
    DIRECTION OUTPUT ;
    USE SIGNAL ;
    SHAPE ABUTMENT ;
    PORT
      LAYER M4 ;
      RECT 103.336 33.264 103.360 33.288 ;
    END
  END rd_out_B[11]
  PIN rd_out_A[12]
    DIRECTION OUTPUT ;
    USE SIGNAL ;
    SHAPE ABUTMENT ;
    PORT
      LAYER M4 ;
      RECT 0.000 33.696 0.024 33.720 ;
    END
  END rd_out_A[12]
  PIN rd_out_B[12]
    DIRECTION OUTPUT ;
    USE SIGNAL ;
    SHAPE ABUTMENT ;
    PORT
      LAYER M4 ;
      RECT 103.336 33.696 103.360 33.720 ;
    END
  END rd_out_B[12]
  PIN rd_out_A[13]
    DIRECTION OUTPUT ;
    USE SIGNAL ;
    SHAPE ABUTMENT ;
    PORT
      LAYER M4 ;
      RECT 0.000 34.128 0.024 34.152 ;
    END
  END rd_out_A[13]
  PIN rd_out_B[13]
    DIRECTION OUTPUT ;
    USE SIGNAL ;
    SHAPE ABUTMENT ;
    PORT
      LAYER M4 ;
      RECT 103.336 34.128 103.360 34.152 ;
    END
  END rd_out_B[13]
  PIN rd_out_A[14]
    DIRECTION OUTPUT ;
    USE SIGNAL ;
    SHAPE ABUTMENT ;
    PORT
      LAYER M4 ;
      RECT 0.000 34.560 0.024 34.584 ;
    END
  END rd_out_A[14]
  PIN rd_out_B[14]
    DIRECTION OUTPUT ;
    USE SIGNAL ;
    SHAPE ABUTMENT ;
    PORT
      LAYER M4 ;
      RECT 103.336 34.560 103.360 34.584 ;
    END
  END rd_out_B[14]
  PIN rd_out_A[15]
    DIRECTION OUTPUT ;
    USE SIGNAL ;
    SHAPE ABUTMENT ;
    PORT
      LAYER M4 ;
      RECT 0.000 34.992 0.024 35.016 ;
    END
  END rd_out_A[15]
  PIN rd_out_B[15]
    DIRECTION OUTPUT ;
    USE SIGNAL ;
    SHAPE ABUTMENT ;
    PORT
      LAYER M4 ;
      RECT 103.336 34.992 103.360 35.016 ;
    END
  END rd_out_B[15]
  PIN rd_out_A[16]
    DIRECTION OUTPUT ;
    USE SIGNAL ;
    SHAPE ABUTMENT ;
    PORT
      LAYER M4 ;
      RECT 0.000 35.424 0.024 35.448 ;
    END
  END rd_out_A[16]
  PIN rd_out_B[16]
    DIRECTION OUTPUT ;
    USE SIGNAL ;
    SHAPE ABUTMENT ;
    PORT
      LAYER M4 ;
      RECT 103.336 35.424 103.360 35.448 ;
    END
  END rd_out_B[16]
  PIN rd_out_A[17]
    DIRECTION OUTPUT ;
    USE SIGNAL ;
    SHAPE ABUTMENT ;
    PORT
      LAYER M4 ;
      RECT 0.000 35.856 0.024 35.880 ;
    END
  END rd_out_A[17]
  PIN rd_out_B[17]
    DIRECTION OUTPUT ;
    USE SIGNAL ;
    SHAPE ABUTMENT ;
    PORT
      LAYER M4 ;
      RECT 103.336 35.856 103.360 35.880 ;
    END
  END rd_out_B[17]
  PIN rd_out_A[18]
    DIRECTION OUTPUT ;
    USE SIGNAL ;
    SHAPE ABUTMENT ;
    PORT
      LAYER M4 ;
      RECT 0.000 36.288 0.024 36.312 ;
    END
  END rd_out_A[18]
  PIN rd_out_B[18]
    DIRECTION OUTPUT ;
    USE SIGNAL ;
    SHAPE ABUTMENT ;
    PORT
      LAYER M4 ;
      RECT 103.336 36.288 103.360 36.312 ;
    END
  END rd_out_B[18]
  PIN rd_out_A[19]
    DIRECTION OUTPUT ;
    USE SIGNAL ;
    SHAPE ABUTMENT ;
    PORT
      LAYER M4 ;
      RECT 0.000 36.720 0.024 36.744 ;
    END
  END rd_out_A[19]
  PIN rd_out_B[19]
    DIRECTION OUTPUT ;
    USE SIGNAL ;
    SHAPE ABUTMENT ;
    PORT
      LAYER M4 ;
      RECT 103.336 36.720 103.360 36.744 ;
    END
  END rd_out_B[19]
  PIN rd_out_A[20]
    DIRECTION OUTPUT ;
    USE SIGNAL ;
    SHAPE ABUTMENT ;
    PORT
      LAYER M4 ;
      RECT 0.000 37.152 0.024 37.176 ;
    END
  END rd_out_A[20]
  PIN rd_out_B[20]
    DIRECTION OUTPUT ;
    USE SIGNAL ;
    SHAPE ABUTMENT ;
    PORT
      LAYER M4 ;
      RECT 103.336 37.152 103.360 37.176 ;
    END
  END rd_out_B[20]
  PIN rd_out_A[21]
    DIRECTION OUTPUT ;
    USE SIGNAL ;
    SHAPE ABUTMENT ;
    PORT
      LAYER M4 ;
      RECT 0.000 37.584 0.024 37.608 ;
    END
  END rd_out_A[21]
  PIN rd_out_B[21]
    DIRECTION OUTPUT ;
    USE SIGNAL ;
    SHAPE ABUTMENT ;
    PORT
      LAYER M4 ;
      RECT 103.336 37.584 103.360 37.608 ;
    END
  END rd_out_B[21]
  PIN rd_out_A[22]
    DIRECTION OUTPUT ;
    USE SIGNAL ;
    SHAPE ABUTMENT ;
    PORT
      LAYER M4 ;
      RECT 0.000 38.016 0.024 38.040 ;
    END
  END rd_out_A[22]
  PIN rd_out_B[22]
    DIRECTION OUTPUT ;
    USE SIGNAL ;
    SHAPE ABUTMENT ;
    PORT
      LAYER M4 ;
      RECT 103.336 38.016 103.360 38.040 ;
    END
  END rd_out_B[22]
  PIN rd_out_A[23]
    DIRECTION OUTPUT ;
    USE SIGNAL ;
    SHAPE ABUTMENT ;
    PORT
      LAYER M4 ;
      RECT 0.000 38.448 0.024 38.472 ;
    END
  END rd_out_A[23]
  PIN rd_out_B[23]
    DIRECTION OUTPUT ;
    USE SIGNAL ;
    SHAPE ABUTMENT ;
    PORT
      LAYER M4 ;
      RECT 103.336 38.448 103.360 38.472 ;
    END
  END rd_out_B[23]
  PIN rd_out_A[24]
    DIRECTION OUTPUT ;
    USE SIGNAL ;
    SHAPE ABUTMENT ;
    PORT
      LAYER M4 ;
      RECT 0.000 38.880 0.024 38.904 ;
    END
  END rd_out_A[24]
  PIN rd_out_B[24]
    DIRECTION OUTPUT ;
    USE SIGNAL ;
    SHAPE ABUTMENT ;
    PORT
      LAYER M4 ;
      RECT 103.336 38.880 103.360 38.904 ;
    END
  END rd_out_B[24]
  PIN rd_out_A[25]
    DIRECTION OUTPUT ;
    USE SIGNAL ;
    SHAPE ABUTMENT ;
    PORT
      LAYER M4 ;
      RECT 0.000 39.312 0.024 39.336 ;
    END
  END rd_out_A[25]
  PIN rd_out_B[25]
    DIRECTION OUTPUT ;
    USE SIGNAL ;
    SHAPE ABUTMENT ;
    PORT
      LAYER M4 ;
      RECT 103.336 39.312 103.360 39.336 ;
    END
  END rd_out_B[25]
  PIN rd_out_A[26]
    DIRECTION OUTPUT ;
    USE SIGNAL ;
    SHAPE ABUTMENT ;
    PORT
      LAYER M4 ;
      RECT 0.000 39.744 0.024 39.768 ;
    END
  END rd_out_A[26]
  PIN rd_out_B[26]
    DIRECTION OUTPUT ;
    USE SIGNAL ;
    SHAPE ABUTMENT ;
    PORT
      LAYER M4 ;
      RECT 103.336 39.744 103.360 39.768 ;
    END
  END rd_out_B[26]
  PIN rd_out_A[27]
    DIRECTION OUTPUT ;
    USE SIGNAL ;
    SHAPE ABUTMENT ;
    PORT
      LAYER M4 ;
      RECT 0.000 40.176 0.024 40.200 ;
    END
  END rd_out_A[27]
  PIN rd_out_B[27]
    DIRECTION OUTPUT ;
    USE SIGNAL ;
    SHAPE ABUTMENT ;
    PORT
      LAYER M4 ;
      RECT 103.336 40.176 103.360 40.200 ;
    END
  END rd_out_B[27]
  PIN rd_out_A[28]
    DIRECTION OUTPUT ;
    USE SIGNAL ;
    SHAPE ABUTMENT ;
    PORT
      LAYER M4 ;
      RECT 0.000 40.608 0.024 40.632 ;
    END
  END rd_out_A[28]
  PIN rd_out_B[28]
    DIRECTION OUTPUT ;
    USE SIGNAL ;
    SHAPE ABUTMENT ;
    PORT
      LAYER M4 ;
      RECT 103.336 40.608 103.360 40.632 ;
    END
  END rd_out_B[28]
  PIN rd_out_A[29]
    DIRECTION OUTPUT ;
    USE SIGNAL ;
    SHAPE ABUTMENT ;
    PORT
      LAYER M4 ;
      RECT 0.000 41.040 0.024 41.064 ;
    END
  END rd_out_A[29]
  PIN rd_out_B[29]
    DIRECTION OUTPUT ;
    USE SIGNAL ;
    SHAPE ABUTMENT ;
    PORT
      LAYER M4 ;
      RECT 103.336 41.040 103.360 41.064 ;
    END
  END rd_out_B[29]
  PIN rd_out_A[30]
    DIRECTION OUTPUT ;
    USE SIGNAL ;
    SHAPE ABUTMENT ;
    PORT
      LAYER M4 ;
      RECT 0.000 41.472 0.024 41.496 ;
    END
  END rd_out_A[30]
  PIN rd_out_B[30]
    DIRECTION OUTPUT ;
    USE SIGNAL ;
    SHAPE ABUTMENT ;
    PORT
      LAYER M4 ;
      RECT 103.336 41.472 103.360 41.496 ;
    END
  END rd_out_B[30]
  PIN rd_out_A[31]
    DIRECTION OUTPUT ;
    USE SIGNAL ;
    SHAPE ABUTMENT ;
    PORT
      LAYER M4 ;
      RECT 0.000 41.904 0.024 41.928 ;
    END
  END rd_out_A[31]
  PIN rd_out_B[31]
    DIRECTION OUTPUT ;
    USE SIGNAL ;
    SHAPE ABUTMENT ;
    PORT
      LAYER M4 ;
      RECT 103.336 41.904 103.360 41.928 ;
    END
  END rd_out_B[31]
  PIN rd_out_A[32]
    DIRECTION OUTPUT ;
    USE SIGNAL ;
    SHAPE ABUTMENT ;
    PORT
      LAYER M4 ;
      RECT 0.000 42.336 0.024 42.360 ;
    END
  END rd_out_A[32]
  PIN rd_out_B[32]
    DIRECTION OUTPUT ;
    USE SIGNAL ;
    SHAPE ABUTMENT ;
    PORT
      LAYER M4 ;
      RECT 103.336 42.336 103.360 42.360 ;
    END
  END rd_out_B[32]
  PIN rd_out_A[33]
    DIRECTION OUTPUT ;
    USE SIGNAL ;
    SHAPE ABUTMENT ;
    PORT
      LAYER M4 ;
      RECT 0.000 42.768 0.024 42.792 ;
    END
  END rd_out_A[33]
  PIN rd_out_B[33]
    DIRECTION OUTPUT ;
    USE SIGNAL ;
    SHAPE ABUTMENT ;
    PORT
      LAYER M4 ;
      RECT 103.336 42.768 103.360 42.792 ;
    END
  END rd_out_B[33]
  PIN rd_out_A[34]
    DIRECTION OUTPUT ;
    USE SIGNAL ;
    SHAPE ABUTMENT ;
    PORT
      LAYER M4 ;
      RECT 0.000 43.200 0.024 43.224 ;
    END
  END rd_out_A[34]
  PIN rd_out_B[34]
    DIRECTION OUTPUT ;
    USE SIGNAL ;
    SHAPE ABUTMENT ;
    PORT
      LAYER M4 ;
      RECT 103.336 43.200 103.360 43.224 ;
    END
  END rd_out_B[34]
  PIN rd_out_A[35]
    DIRECTION OUTPUT ;
    USE SIGNAL ;
    SHAPE ABUTMENT ;
    PORT
      LAYER M4 ;
      RECT 0.000 43.632 0.024 43.656 ;
    END
  END rd_out_A[35]
  PIN rd_out_B[35]
    DIRECTION OUTPUT ;
    USE SIGNAL ;
    SHAPE ABUTMENT ;
    PORT
      LAYER M4 ;
      RECT 103.336 43.632 103.360 43.656 ;
    END
  END rd_out_B[35]
  PIN rd_out_A[36]
    DIRECTION OUTPUT ;
    USE SIGNAL ;
    SHAPE ABUTMENT ;
    PORT
      LAYER M4 ;
      RECT 0.000 44.064 0.024 44.088 ;
    END
  END rd_out_A[36]
  PIN rd_out_B[36]
    DIRECTION OUTPUT ;
    USE SIGNAL ;
    SHAPE ABUTMENT ;
    PORT
      LAYER M4 ;
      RECT 103.336 44.064 103.360 44.088 ;
    END
  END rd_out_B[36]
  PIN rd_out_A[37]
    DIRECTION OUTPUT ;
    USE SIGNAL ;
    SHAPE ABUTMENT ;
    PORT
      LAYER M4 ;
      RECT 0.000 44.496 0.024 44.520 ;
    END
  END rd_out_A[37]
  PIN rd_out_B[37]
    DIRECTION OUTPUT ;
    USE SIGNAL ;
    SHAPE ABUTMENT ;
    PORT
      LAYER M4 ;
      RECT 103.336 44.496 103.360 44.520 ;
    END
  END rd_out_B[37]
  PIN rd_out_A[38]
    DIRECTION OUTPUT ;
    USE SIGNAL ;
    SHAPE ABUTMENT ;
    PORT
      LAYER M4 ;
      RECT 0.000 44.928 0.024 44.952 ;
    END
  END rd_out_A[38]
  PIN rd_out_B[38]
    DIRECTION OUTPUT ;
    USE SIGNAL ;
    SHAPE ABUTMENT ;
    PORT
      LAYER M4 ;
      RECT 103.336 44.928 103.360 44.952 ;
    END
  END rd_out_B[38]
  PIN rd_out_A[39]
    DIRECTION OUTPUT ;
    USE SIGNAL ;
    SHAPE ABUTMENT ;
    PORT
      LAYER M4 ;
      RECT 0.000 45.360 0.024 45.384 ;
    END
  END rd_out_A[39]
  PIN rd_out_B[39]
    DIRECTION OUTPUT ;
    USE SIGNAL ;
    SHAPE ABUTMENT ;
    PORT
      LAYER M4 ;
      RECT 103.336 45.360 103.360 45.384 ;
    END
  END rd_out_B[39]
  PIN rd_out_A[40]
    DIRECTION OUTPUT ;
    USE SIGNAL ;
    SHAPE ABUTMENT ;
    PORT
      LAYER M4 ;
      RECT 0.000 45.792 0.024 45.816 ;
    END
  END rd_out_A[40]
  PIN rd_out_B[40]
    DIRECTION OUTPUT ;
    USE SIGNAL ;
    SHAPE ABUTMENT ;
    PORT
      LAYER M4 ;
      RECT 103.336 45.792 103.360 45.816 ;
    END
  END rd_out_B[40]
  PIN rd_out_A[41]
    DIRECTION OUTPUT ;
    USE SIGNAL ;
    SHAPE ABUTMENT ;
    PORT
      LAYER M4 ;
      RECT 0.000 46.224 0.024 46.248 ;
    END
  END rd_out_A[41]
  PIN rd_out_B[41]
    DIRECTION OUTPUT ;
    USE SIGNAL ;
    SHAPE ABUTMENT ;
    PORT
      LAYER M4 ;
      RECT 103.336 46.224 103.360 46.248 ;
    END
  END rd_out_B[41]
  PIN rd_out_A[42]
    DIRECTION OUTPUT ;
    USE SIGNAL ;
    SHAPE ABUTMENT ;
    PORT
      LAYER M4 ;
      RECT 0.000 46.656 0.024 46.680 ;
    END
  END rd_out_A[42]
  PIN rd_out_B[42]
    DIRECTION OUTPUT ;
    USE SIGNAL ;
    SHAPE ABUTMENT ;
    PORT
      LAYER M4 ;
      RECT 103.336 46.656 103.360 46.680 ;
    END
  END rd_out_B[42]
  PIN rd_out_A[43]
    DIRECTION OUTPUT ;
    USE SIGNAL ;
    SHAPE ABUTMENT ;
    PORT
      LAYER M4 ;
      RECT 0.000 47.088 0.024 47.112 ;
    END
  END rd_out_A[43]
  PIN rd_out_B[43]
    DIRECTION OUTPUT ;
    USE SIGNAL ;
    SHAPE ABUTMENT ;
    PORT
      LAYER M4 ;
      RECT 103.336 47.088 103.360 47.112 ;
    END
  END rd_out_B[43]
  PIN rd_out_A[44]
    DIRECTION OUTPUT ;
    USE SIGNAL ;
    SHAPE ABUTMENT ;
    PORT
      LAYER M4 ;
      RECT 0.000 47.520 0.024 47.544 ;
    END
  END rd_out_A[44]
  PIN rd_out_B[44]
    DIRECTION OUTPUT ;
    USE SIGNAL ;
    SHAPE ABUTMENT ;
    PORT
      LAYER M4 ;
      RECT 103.336 47.520 103.360 47.544 ;
    END
  END rd_out_B[44]
  PIN rd_out_A[45]
    DIRECTION OUTPUT ;
    USE SIGNAL ;
    SHAPE ABUTMENT ;
    PORT
      LAYER M4 ;
      RECT 0.000 47.952 0.024 47.976 ;
    END
  END rd_out_A[45]
  PIN rd_out_B[45]
    DIRECTION OUTPUT ;
    USE SIGNAL ;
    SHAPE ABUTMENT ;
    PORT
      LAYER M4 ;
      RECT 103.336 47.952 103.360 47.976 ;
    END
  END rd_out_B[45]
  PIN rd_out_A[46]
    DIRECTION OUTPUT ;
    USE SIGNAL ;
    SHAPE ABUTMENT ;
    PORT
      LAYER M4 ;
      RECT 0.000 48.384 0.024 48.408 ;
    END
  END rd_out_A[46]
  PIN rd_out_B[46]
    DIRECTION OUTPUT ;
    USE SIGNAL ;
    SHAPE ABUTMENT ;
    PORT
      LAYER M4 ;
      RECT 103.336 48.384 103.360 48.408 ;
    END
  END rd_out_B[46]
  PIN rd_out_A[47]
    DIRECTION OUTPUT ;
    USE SIGNAL ;
    SHAPE ABUTMENT ;
    PORT
      LAYER M4 ;
      RECT 0.000 48.816 0.024 48.840 ;
    END
  END rd_out_A[47]
  PIN rd_out_B[47]
    DIRECTION OUTPUT ;
    USE SIGNAL ;
    SHAPE ABUTMENT ;
    PORT
      LAYER M4 ;
      RECT 103.336 48.816 103.360 48.840 ;
    END
  END rd_out_B[47]
  PIN rd_out_A[48]
    DIRECTION OUTPUT ;
    USE SIGNAL ;
    SHAPE ABUTMENT ;
    PORT
      LAYER M4 ;
      RECT 0.000 49.248 0.024 49.272 ;
    END
  END rd_out_A[48]
  PIN rd_out_B[48]
    DIRECTION OUTPUT ;
    USE SIGNAL ;
    SHAPE ABUTMENT ;
    PORT
      LAYER M4 ;
      RECT 103.336 49.248 103.360 49.272 ;
    END
  END rd_out_B[48]
  PIN rd_out_A[49]
    DIRECTION OUTPUT ;
    USE SIGNAL ;
    SHAPE ABUTMENT ;
    PORT
      LAYER M4 ;
      RECT 0.000 49.680 0.024 49.704 ;
    END
  END rd_out_A[49]
  PIN rd_out_B[49]
    DIRECTION OUTPUT ;
    USE SIGNAL ;
    SHAPE ABUTMENT ;
    PORT
      LAYER M4 ;
      RECT 103.336 49.680 103.360 49.704 ;
    END
  END rd_out_B[49]
  PIN rd_out_A[50]
    DIRECTION OUTPUT ;
    USE SIGNAL ;
    SHAPE ABUTMENT ;
    PORT
      LAYER M4 ;
      RECT 0.000 50.112 0.024 50.136 ;
    END
  END rd_out_A[50]
  PIN rd_out_B[50]
    DIRECTION OUTPUT ;
    USE SIGNAL ;
    SHAPE ABUTMENT ;
    PORT
      LAYER M4 ;
      RECT 103.336 50.112 103.360 50.136 ;
    END
  END rd_out_B[50]
  PIN rd_out_A[51]
    DIRECTION OUTPUT ;
    USE SIGNAL ;
    SHAPE ABUTMENT ;
    PORT
      LAYER M4 ;
      RECT 0.000 50.544 0.024 50.568 ;
    END
  END rd_out_A[51]
  PIN rd_out_B[51]
    DIRECTION OUTPUT ;
    USE SIGNAL ;
    SHAPE ABUTMENT ;
    PORT
      LAYER M4 ;
      RECT 103.336 50.544 103.360 50.568 ;
    END
  END rd_out_B[51]
  PIN rd_out_A[52]
    DIRECTION OUTPUT ;
    USE SIGNAL ;
    SHAPE ABUTMENT ;
    PORT
      LAYER M4 ;
      RECT 0.000 50.976 0.024 51.000 ;
    END
  END rd_out_A[52]
  PIN rd_out_B[52]
    DIRECTION OUTPUT ;
    USE SIGNAL ;
    SHAPE ABUTMENT ;
    PORT
      LAYER M4 ;
      RECT 103.336 50.976 103.360 51.000 ;
    END
  END rd_out_B[52]
  PIN rd_out_A[53]
    DIRECTION OUTPUT ;
    USE SIGNAL ;
    SHAPE ABUTMENT ;
    PORT
      LAYER M4 ;
      RECT 0.000 51.408 0.024 51.432 ;
    END
  END rd_out_A[53]
  PIN rd_out_B[53]
    DIRECTION OUTPUT ;
    USE SIGNAL ;
    SHAPE ABUTMENT ;
    PORT
      LAYER M4 ;
      RECT 103.336 51.408 103.360 51.432 ;
    END
  END rd_out_B[53]
  PIN rd_out_A[54]
    DIRECTION OUTPUT ;
    USE SIGNAL ;
    SHAPE ABUTMENT ;
    PORT
      LAYER M4 ;
      RECT 0.000 51.840 0.024 51.864 ;
    END
  END rd_out_A[54]
  PIN rd_out_B[54]
    DIRECTION OUTPUT ;
    USE SIGNAL ;
    SHAPE ABUTMENT ;
    PORT
      LAYER M4 ;
      RECT 103.336 51.840 103.360 51.864 ;
    END
  END rd_out_B[54]
  PIN rd_out_A[55]
    DIRECTION OUTPUT ;
    USE SIGNAL ;
    SHAPE ABUTMENT ;
    PORT
      LAYER M4 ;
      RECT 0.000 52.272 0.024 52.296 ;
    END
  END rd_out_A[55]
  PIN rd_out_B[55]
    DIRECTION OUTPUT ;
    USE SIGNAL ;
    SHAPE ABUTMENT ;
    PORT
      LAYER M4 ;
      RECT 103.336 52.272 103.360 52.296 ;
    END
  END rd_out_B[55]
  PIN rd_out_A[56]
    DIRECTION OUTPUT ;
    USE SIGNAL ;
    SHAPE ABUTMENT ;
    PORT
      LAYER M4 ;
      RECT 0.000 52.704 0.024 52.728 ;
    END
  END rd_out_A[56]
  PIN rd_out_B[56]
    DIRECTION OUTPUT ;
    USE SIGNAL ;
    SHAPE ABUTMENT ;
    PORT
      LAYER M4 ;
      RECT 103.336 52.704 103.360 52.728 ;
    END
  END rd_out_B[56]
  PIN rd_out_A[57]
    DIRECTION OUTPUT ;
    USE SIGNAL ;
    SHAPE ABUTMENT ;
    PORT
      LAYER M4 ;
      RECT 0.000 53.136 0.024 53.160 ;
    END
  END rd_out_A[57]
  PIN rd_out_B[57]
    DIRECTION OUTPUT ;
    USE SIGNAL ;
    SHAPE ABUTMENT ;
    PORT
      LAYER M4 ;
      RECT 103.336 53.136 103.360 53.160 ;
    END
  END rd_out_B[57]
  PIN rd_out_A[58]
    DIRECTION OUTPUT ;
    USE SIGNAL ;
    SHAPE ABUTMENT ;
    PORT
      LAYER M4 ;
      RECT 0.000 53.568 0.024 53.592 ;
    END
  END rd_out_A[58]
  PIN rd_out_B[58]
    DIRECTION OUTPUT ;
    USE SIGNAL ;
    SHAPE ABUTMENT ;
    PORT
      LAYER M4 ;
      RECT 103.336 53.568 103.360 53.592 ;
    END
  END rd_out_B[58]
  PIN rd_out_A[59]
    DIRECTION OUTPUT ;
    USE SIGNAL ;
    SHAPE ABUTMENT ;
    PORT
      LAYER M4 ;
      RECT 0.000 54.000 0.024 54.024 ;
    END
  END rd_out_A[59]
  PIN rd_out_B[59]
    DIRECTION OUTPUT ;
    USE SIGNAL ;
    SHAPE ABUTMENT ;
    PORT
      LAYER M4 ;
      RECT 103.336 54.000 103.360 54.024 ;
    END
  END rd_out_B[59]
  PIN rd_out_A[60]
    DIRECTION OUTPUT ;
    USE SIGNAL ;
    SHAPE ABUTMENT ;
    PORT
      LAYER M4 ;
      RECT 0.000 54.432 0.024 54.456 ;
    END
  END rd_out_A[60]
  PIN rd_out_B[60]
    DIRECTION OUTPUT ;
    USE SIGNAL ;
    SHAPE ABUTMENT ;
    PORT
      LAYER M4 ;
      RECT 103.336 54.432 103.360 54.456 ;
    END
  END rd_out_B[60]
  PIN rd_out_A[61]
    DIRECTION OUTPUT ;
    USE SIGNAL ;
    SHAPE ABUTMENT ;
    PORT
      LAYER M4 ;
      RECT 0.000 54.864 0.024 54.888 ;
    END
  END rd_out_A[61]
  PIN rd_out_B[61]
    DIRECTION OUTPUT ;
    USE SIGNAL ;
    SHAPE ABUTMENT ;
    PORT
      LAYER M4 ;
      RECT 103.336 54.864 103.360 54.888 ;
    END
  END rd_out_B[61]
  PIN rd_out_A[62]
    DIRECTION OUTPUT ;
    USE SIGNAL ;
    SHAPE ABUTMENT ;
    PORT
      LAYER M4 ;
      RECT 0.000 55.296 0.024 55.320 ;
    END
  END rd_out_A[62]
  PIN rd_out_B[62]
    DIRECTION OUTPUT ;
    USE SIGNAL ;
    SHAPE ABUTMENT ;
    PORT
      LAYER M4 ;
      RECT 103.336 55.296 103.360 55.320 ;
    END
  END rd_out_B[62]
  PIN rd_out_A[63]
    DIRECTION OUTPUT ;
    USE SIGNAL ;
    SHAPE ABUTMENT ;
    PORT
      LAYER M4 ;
      RECT 0.000 55.728 0.024 55.752 ;
    END
  END rd_out_A[63]
  PIN rd_out_B[63]
    DIRECTION OUTPUT ;
    USE SIGNAL ;
    SHAPE ABUTMENT ;
    PORT
      LAYER M4 ;
      RECT 103.336 55.728 103.360 55.752 ;
    END
  END rd_out_B[63]
  PIN wd_in_A[0]
    DIRECTION INPUT ;
    USE SIGNAL ;
    SHAPE ABUTMENT ;
    PORT
      LAYER M4 ;
      RECT 0.000 56.976 0.024 57.000 ;
    END
  END wd_in_A[0]
  PIN wd_in_B[0]
    DIRECTION INPUT ;
    USE SIGNAL ;
    SHAPE ABUTMENT ;
    PORT
      LAYER M4 ;
      RECT 103.336 56.976 103.360 57.000 ;
    END
  END wd_in_B[0]
  PIN wd_in_A[1]
    DIRECTION INPUT ;
    USE SIGNAL ;
    SHAPE ABUTMENT ;
    PORT
      LAYER M4 ;
      RECT 0.000 57.408 0.024 57.432 ;
    END
  END wd_in_A[1]
  PIN wd_in_B[1]
    DIRECTION INPUT ;
    USE SIGNAL ;
    SHAPE ABUTMENT ;
    PORT
      LAYER M4 ;
      RECT 103.336 57.408 103.360 57.432 ;
    END
  END wd_in_B[1]
  PIN wd_in_A[2]
    DIRECTION INPUT ;
    USE SIGNAL ;
    SHAPE ABUTMENT ;
    PORT
      LAYER M4 ;
      RECT 0.000 57.840 0.024 57.864 ;
    END
  END wd_in_A[2]
  PIN wd_in_B[2]
    DIRECTION INPUT ;
    USE SIGNAL ;
    SHAPE ABUTMENT ;
    PORT
      LAYER M4 ;
      RECT 103.336 57.840 103.360 57.864 ;
    END
  END wd_in_B[2]
  PIN wd_in_A[3]
    DIRECTION INPUT ;
    USE SIGNAL ;
    SHAPE ABUTMENT ;
    PORT
      LAYER M4 ;
      RECT 0.000 58.272 0.024 58.296 ;
    END
  END wd_in_A[3]
  PIN wd_in_B[3]
    DIRECTION INPUT ;
    USE SIGNAL ;
    SHAPE ABUTMENT ;
    PORT
      LAYER M4 ;
      RECT 103.336 58.272 103.360 58.296 ;
    END
  END wd_in_B[3]
  PIN wd_in_A[4]
    DIRECTION INPUT ;
    USE SIGNAL ;
    SHAPE ABUTMENT ;
    PORT
      LAYER M4 ;
      RECT 0.000 58.704 0.024 58.728 ;
    END
  END wd_in_A[4]
  PIN wd_in_B[4]
    DIRECTION INPUT ;
    USE SIGNAL ;
    SHAPE ABUTMENT ;
    PORT
      LAYER M4 ;
      RECT 103.336 58.704 103.360 58.728 ;
    END
  END wd_in_B[4]
  PIN wd_in_A[5]
    DIRECTION INPUT ;
    USE SIGNAL ;
    SHAPE ABUTMENT ;
    PORT
      LAYER M4 ;
      RECT 0.000 59.136 0.024 59.160 ;
    END
  END wd_in_A[5]
  PIN wd_in_B[5]
    DIRECTION INPUT ;
    USE SIGNAL ;
    SHAPE ABUTMENT ;
    PORT
      LAYER M4 ;
      RECT 103.336 59.136 103.360 59.160 ;
    END
  END wd_in_B[5]
  PIN wd_in_A[6]
    DIRECTION INPUT ;
    USE SIGNAL ;
    SHAPE ABUTMENT ;
    PORT
      LAYER M4 ;
      RECT 0.000 59.568 0.024 59.592 ;
    END
  END wd_in_A[6]
  PIN wd_in_B[6]
    DIRECTION INPUT ;
    USE SIGNAL ;
    SHAPE ABUTMENT ;
    PORT
      LAYER M4 ;
      RECT 103.336 59.568 103.360 59.592 ;
    END
  END wd_in_B[6]
  PIN wd_in_A[7]
    DIRECTION INPUT ;
    USE SIGNAL ;
    SHAPE ABUTMENT ;
    PORT
      LAYER M4 ;
      RECT 0.000 60.000 0.024 60.024 ;
    END
  END wd_in_A[7]
  PIN wd_in_B[7]
    DIRECTION INPUT ;
    USE SIGNAL ;
    SHAPE ABUTMENT ;
    PORT
      LAYER M4 ;
      RECT 103.336 60.000 103.360 60.024 ;
    END
  END wd_in_B[7]
  PIN wd_in_A[8]
    DIRECTION INPUT ;
    USE SIGNAL ;
    SHAPE ABUTMENT ;
    PORT
      LAYER M4 ;
      RECT 0.000 60.432 0.024 60.456 ;
    END
  END wd_in_A[8]
  PIN wd_in_B[8]
    DIRECTION INPUT ;
    USE SIGNAL ;
    SHAPE ABUTMENT ;
    PORT
      LAYER M4 ;
      RECT 103.336 60.432 103.360 60.456 ;
    END
  END wd_in_B[8]
  PIN wd_in_A[9]
    DIRECTION INPUT ;
    USE SIGNAL ;
    SHAPE ABUTMENT ;
    PORT
      LAYER M4 ;
      RECT 0.000 60.864 0.024 60.888 ;
    END
  END wd_in_A[9]
  PIN wd_in_B[9]
    DIRECTION INPUT ;
    USE SIGNAL ;
    SHAPE ABUTMENT ;
    PORT
      LAYER M4 ;
      RECT 103.336 60.864 103.360 60.888 ;
    END
  END wd_in_B[9]
  PIN wd_in_A[10]
    DIRECTION INPUT ;
    USE SIGNAL ;
    SHAPE ABUTMENT ;
    PORT
      LAYER M4 ;
      RECT 0.000 61.296 0.024 61.320 ;
    END
  END wd_in_A[10]
  PIN wd_in_B[10]
    DIRECTION INPUT ;
    USE SIGNAL ;
    SHAPE ABUTMENT ;
    PORT
      LAYER M4 ;
      RECT 103.336 61.296 103.360 61.320 ;
    END
  END wd_in_B[10]
  PIN wd_in_A[11]
    DIRECTION INPUT ;
    USE SIGNAL ;
    SHAPE ABUTMENT ;
    PORT
      LAYER M4 ;
      RECT 0.000 61.728 0.024 61.752 ;
    END
  END wd_in_A[11]
  PIN wd_in_B[11]
    DIRECTION INPUT ;
    USE SIGNAL ;
    SHAPE ABUTMENT ;
    PORT
      LAYER M4 ;
      RECT 103.336 61.728 103.360 61.752 ;
    END
  END wd_in_B[11]
  PIN wd_in_A[12]
    DIRECTION INPUT ;
    USE SIGNAL ;
    SHAPE ABUTMENT ;
    PORT
      LAYER M4 ;
      RECT 0.000 62.160 0.024 62.184 ;
    END
  END wd_in_A[12]
  PIN wd_in_B[12]
    DIRECTION INPUT ;
    USE SIGNAL ;
    SHAPE ABUTMENT ;
    PORT
      LAYER M4 ;
      RECT 103.336 62.160 103.360 62.184 ;
    END
  END wd_in_B[12]
  PIN wd_in_A[13]
    DIRECTION INPUT ;
    USE SIGNAL ;
    SHAPE ABUTMENT ;
    PORT
      LAYER M4 ;
      RECT 0.000 62.592 0.024 62.616 ;
    END
  END wd_in_A[13]
  PIN wd_in_B[13]
    DIRECTION INPUT ;
    USE SIGNAL ;
    SHAPE ABUTMENT ;
    PORT
      LAYER M4 ;
      RECT 103.336 62.592 103.360 62.616 ;
    END
  END wd_in_B[13]
  PIN wd_in_A[14]
    DIRECTION INPUT ;
    USE SIGNAL ;
    SHAPE ABUTMENT ;
    PORT
      LAYER M4 ;
      RECT 0.000 63.024 0.024 63.048 ;
    END
  END wd_in_A[14]
  PIN wd_in_B[14]
    DIRECTION INPUT ;
    USE SIGNAL ;
    SHAPE ABUTMENT ;
    PORT
      LAYER M4 ;
      RECT 103.336 63.024 103.360 63.048 ;
    END
  END wd_in_B[14]
  PIN wd_in_A[15]
    DIRECTION INPUT ;
    USE SIGNAL ;
    SHAPE ABUTMENT ;
    PORT
      LAYER M4 ;
      RECT 0.000 63.456 0.024 63.480 ;
    END
  END wd_in_A[15]
  PIN wd_in_B[15]
    DIRECTION INPUT ;
    USE SIGNAL ;
    SHAPE ABUTMENT ;
    PORT
      LAYER M4 ;
      RECT 103.336 63.456 103.360 63.480 ;
    END
  END wd_in_B[15]
  PIN wd_in_A[16]
    DIRECTION INPUT ;
    USE SIGNAL ;
    SHAPE ABUTMENT ;
    PORT
      LAYER M4 ;
      RECT 0.000 63.888 0.024 63.912 ;
    END
  END wd_in_A[16]
  PIN wd_in_B[16]
    DIRECTION INPUT ;
    USE SIGNAL ;
    SHAPE ABUTMENT ;
    PORT
      LAYER M4 ;
      RECT 103.336 63.888 103.360 63.912 ;
    END
  END wd_in_B[16]
  PIN wd_in_A[17]
    DIRECTION INPUT ;
    USE SIGNAL ;
    SHAPE ABUTMENT ;
    PORT
      LAYER M4 ;
      RECT 0.000 64.320 0.024 64.344 ;
    END
  END wd_in_A[17]
  PIN wd_in_B[17]
    DIRECTION INPUT ;
    USE SIGNAL ;
    SHAPE ABUTMENT ;
    PORT
      LAYER M4 ;
      RECT 103.336 64.320 103.360 64.344 ;
    END
  END wd_in_B[17]
  PIN wd_in_A[18]
    DIRECTION INPUT ;
    USE SIGNAL ;
    SHAPE ABUTMENT ;
    PORT
      LAYER M4 ;
      RECT 0.000 64.752 0.024 64.776 ;
    END
  END wd_in_A[18]
  PIN wd_in_B[18]
    DIRECTION INPUT ;
    USE SIGNAL ;
    SHAPE ABUTMENT ;
    PORT
      LAYER M4 ;
      RECT 103.336 64.752 103.360 64.776 ;
    END
  END wd_in_B[18]
  PIN wd_in_A[19]
    DIRECTION INPUT ;
    USE SIGNAL ;
    SHAPE ABUTMENT ;
    PORT
      LAYER M4 ;
      RECT 0.000 65.184 0.024 65.208 ;
    END
  END wd_in_A[19]
  PIN wd_in_B[19]
    DIRECTION INPUT ;
    USE SIGNAL ;
    SHAPE ABUTMENT ;
    PORT
      LAYER M4 ;
      RECT 103.336 65.184 103.360 65.208 ;
    END
  END wd_in_B[19]
  PIN wd_in_A[20]
    DIRECTION INPUT ;
    USE SIGNAL ;
    SHAPE ABUTMENT ;
    PORT
      LAYER M4 ;
      RECT 0.000 65.616 0.024 65.640 ;
    END
  END wd_in_A[20]
  PIN wd_in_B[20]
    DIRECTION INPUT ;
    USE SIGNAL ;
    SHAPE ABUTMENT ;
    PORT
      LAYER M4 ;
      RECT 103.336 65.616 103.360 65.640 ;
    END
  END wd_in_B[20]
  PIN wd_in_A[21]
    DIRECTION INPUT ;
    USE SIGNAL ;
    SHAPE ABUTMENT ;
    PORT
      LAYER M4 ;
      RECT 0.000 66.048 0.024 66.072 ;
    END
  END wd_in_A[21]
  PIN wd_in_B[21]
    DIRECTION INPUT ;
    USE SIGNAL ;
    SHAPE ABUTMENT ;
    PORT
      LAYER M4 ;
      RECT 103.336 66.048 103.360 66.072 ;
    END
  END wd_in_B[21]
  PIN wd_in_A[22]
    DIRECTION INPUT ;
    USE SIGNAL ;
    SHAPE ABUTMENT ;
    PORT
      LAYER M4 ;
      RECT 0.000 66.480 0.024 66.504 ;
    END
  END wd_in_A[22]
  PIN wd_in_B[22]
    DIRECTION INPUT ;
    USE SIGNAL ;
    SHAPE ABUTMENT ;
    PORT
      LAYER M4 ;
      RECT 103.336 66.480 103.360 66.504 ;
    END
  END wd_in_B[22]
  PIN wd_in_A[23]
    DIRECTION INPUT ;
    USE SIGNAL ;
    SHAPE ABUTMENT ;
    PORT
      LAYER M4 ;
      RECT 0.000 66.912 0.024 66.936 ;
    END
  END wd_in_A[23]
  PIN wd_in_B[23]
    DIRECTION INPUT ;
    USE SIGNAL ;
    SHAPE ABUTMENT ;
    PORT
      LAYER M4 ;
      RECT 103.336 66.912 103.360 66.936 ;
    END
  END wd_in_B[23]
  PIN wd_in_A[24]
    DIRECTION INPUT ;
    USE SIGNAL ;
    SHAPE ABUTMENT ;
    PORT
      LAYER M4 ;
      RECT 0.000 67.344 0.024 67.368 ;
    END
  END wd_in_A[24]
  PIN wd_in_B[24]
    DIRECTION INPUT ;
    USE SIGNAL ;
    SHAPE ABUTMENT ;
    PORT
      LAYER M4 ;
      RECT 103.336 67.344 103.360 67.368 ;
    END
  END wd_in_B[24]
  PIN wd_in_A[25]
    DIRECTION INPUT ;
    USE SIGNAL ;
    SHAPE ABUTMENT ;
    PORT
      LAYER M4 ;
      RECT 0.000 67.776 0.024 67.800 ;
    END
  END wd_in_A[25]
  PIN wd_in_B[25]
    DIRECTION INPUT ;
    USE SIGNAL ;
    SHAPE ABUTMENT ;
    PORT
      LAYER M4 ;
      RECT 103.336 67.776 103.360 67.800 ;
    END
  END wd_in_B[25]
  PIN wd_in_A[26]
    DIRECTION INPUT ;
    USE SIGNAL ;
    SHAPE ABUTMENT ;
    PORT
      LAYER M4 ;
      RECT 0.000 68.208 0.024 68.232 ;
    END
  END wd_in_A[26]
  PIN wd_in_B[26]
    DIRECTION INPUT ;
    USE SIGNAL ;
    SHAPE ABUTMENT ;
    PORT
      LAYER M4 ;
      RECT 103.336 68.208 103.360 68.232 ;
    END
  END wd_in_B[26]
  PIN wd_in_A[27]
    DIRECTION INPUT ;
    USE SIGNAL ;
    SHAPE ABUTMENT ;
    PORT
      LAYER M4 ;
      RECT 0.000 68.640 0.024 68.664 ;
    END
  END wd_in_A[27]
  PIN wd_in_B[27]
    DIRECTION INPUT ;
    USE SIGNAL ;
    SHAPE ABUTMENT ;
    PORT
      LAYER M4 ;
      RECT 103.336 68.640 103.360 68.664 ;
    END
  END wd_in_B[27]
  PIN wd_in_A[28]
    DIRECTION INPUT ;
    USE SIGNAL ;
    SHAPE ABUTMENT ;
    PORT
      LAYER M4 ;
      RECT 0.000 69.072 0.024 69.096 ;
    END
  END wd_in_A[28]
  PIN wd_in_B[28]
    DIRECTION INPUT ;
    USE SIGNAL ;
    SHAPE ABUTMENT ;
    PORT
      LAYER M4 ;
      RECT 103.336 69.072 103.360 69.096 ;
    END
  END wd_in_B[28]
  PIN wd_in_A[29]
    DIRECTION INPUT ;
    USE SIGNAL ;
    SHAPE ABUTMENT ;
    PORT
      LAYER M4 ;
      RECT 0.000 69.504 0.024 69.528 ;
    END
  END wd_in_A[29]
  PIN wd_in_B[29]
    DIRECTION INPUT ;
    USE SIGNAL ;
    SHAPE ABUTMENT ;
    PORT
      LAYER M4 ;
      RECT 103.336 69.504 103.360 69.528 ;
    END
  END wd_in_B[29]
  PIN wd_in_A[30]
    DIRECTION INPUT ;
    USE SIGNAL ;
    SHAPE ABUTMENT ;
    PORT
      LAYER M4 ;
      RECT 0.000 69.936 0.024 69.960 ;
    END
  END wd_in_A[30]
  PIN wd_in_B[30]
    DIRECTION INPUT ;
    USE SIGNAL ;
    SHAPE ABUTMENT ;
    PORT
      LAYER M4 ;
      RECT 103.336 69.936 103.360 69.960 ;
    END
  END wd_in_B[30]
  PIN wd_in_A[31]
    DIRECTION INPUT ;
    USE SIGNAL ;
    SHAPE ABUTMENT ;
    PORT
      LAYER M4 ;
      RECT 0.000 70.368 0.024 70.392 ;
    END
  END wd_in_A[31]
  PIN wd_in_B[31]
    DIRECTION INPUT ;
    USE SIGNAL ;
    SHAPE ABUTMENT ;
    PORT
      LAYER M4 ;
      RECT 103.336 70.368 103.360 70.392 ;
    END
  END wd_in_B[31]
  PIN wd_in_A[32]
    DIRECTION INPUT ;
    USE SIGNAL ;
    SHAPE ABUTMENT ;
    PORT
      LAYER M4 ;
      RECT 0.000 70.800 0.024 70.824 ;
    END
  END wd_in_A[32]
  PIN wd_in_B[32]
    DIRECTION INPUT ;
    USE SIGNAL ;
    SHAPE ABUTMENT ;
    PORT
      LAYER M4 ;
      RECT 103.336 70.800 103.360 70.824 ;
    END
  END wd_in_B[32]
  PIN wd_in_A[33]
    DIRECTION INPUT ;
    USE SIGNAL ;
    SHAPE ABUTMENT ;
    PORT
      LAYER M4 ;
      RECT 0.000 71.232 0.024 71.256 ;
    END
  END wd_in_A[33]
  PIN wd_in_B[33]
    DIRECTION INPUT ;
    USE SIGNAL ;
    SHAPE ABUTMENT ;
    PORT
      LAYER M4 ;
      RECT 103.336 71.232 103.360 71.256 ;
    END
  END wd_in_B[33]
  PIN wd_in_A[34]
    DIRECTION INPUT ;
    USE SIGNAL ;
    SHAPE ABUTMENT ;
    PORT
      LAYER M4 ;
      RECT 0.000 71.664 0.024 71.688 ;
    END
  END wd_in_A[34]
  PIN wd_in_B[34]
    DIRECTION INPUT ;
    USE SIGNAL ;
    SHAPE ABUTMENT ;
    PORT
      LAYER M4 ;
      RECT 103.336 71.664 103.360 71.688 ;
    END
  END wd_in_B[34]
  PIN wd_in_A[35]
    DIRECTION INPUT ;
    USE SIGNAL ;
    SHAPE ABUTMENT ;
    PORT
      LAYER M4 ;
      RECT 0.000 72.096 0.024 72.120 ;
    END
  END wd_in_A[35]
  PIN wd_in_B[35]
    DIRECTION INPUT ;
    USE SIGNAL ;
    SHAPE ABUTMENT ;
    PORT
      LAYER M4 ;
      RECT 103.336 72.096 103.360 72.120 ;
    END
  END wd_in_B[35]
  PIN wd_in_A[36]
    DIRECTION INPUT ;
    USE SIGNAL ;
    SHAPE ABUTMENT ;
    PORT
      LAYER M4 ;
      RECT 0.000 72.528 0.024 72.552 ;
    END
  END wd_in_A[36]
  PIN wd_in_B[36]
    DIRECTION INPUT ;
    USE SIGNAL ;
    SHAPE ABUTMENT ;
    PORT
      LAYER M4 ;
      RECT 103.336 72.528 103.360 72.552 ;
    END
  END wd_in_B[36]
  PIN wd_in_A[37]
    DIRECTION INPUT ;
    USE SIGNAL ;
    SHAPE ABUTMENT ;
    PORT
      LAYER M4 ;
      RECT 0.000 72.960 0.024 72.984 ;
    END
  END wd_in_A[37]
  PIN wd_in_B[37]
    DIRECTION INPUT ;
    USE SIGNAL ;
    SHAPE ABUTMENT ;
    PORT
      LAYER M4 ;
      RECT 103.336 72.960 103.360 72.984 ;
    END
  END wd_in_B[37]
  PIN wd_in_A[38]
    DIRECTION INPUT ;
    USE SIGNAL ;
    SHAPE ABUTMENT ;
    PORT
      LAYER M4 ;
      RECT 0.000 73.392 0.024 73.416 ;
    END
  END wd_in_A[38]
  PIN wd_in_B[38]
    DIRECTION INPUT ;
    USE SIGNAL ;
    SHAPE ABUTMENT ;
    PORT
      LAYER M4 ;
      RECT 103.336 73.392 103.360 73.416 ;
    END
  END wd_in_B[38]
  PIN wd_in_A[39]
    DIRECTION INPUT ;
    USE SIGNAL ;
    SHAPE ABUTMENT ;
    PORT
      LAYER M4 ;
      RECT 0.000 73.824 0.024 73.848 ;
    END
  END wd_in_A[39]
  PIN wd_in_B[39]
    DIRECTION INPUT ;
    USE SIGNAL ;
    SHAPE ABUTMENT ;
    PORT
      LAYER M4 ;
      RECT 103.336 73.824 103.360 73.848 ;
    END
  END wd_in_B[39]
  PIN wd_in_A[40]
    DIRECTION INPUT ;
    USE SIGNAL ;
    SHAPE ABUTMENT ;
    PORT
      LAYER M4 ;
      RECT 0.000 74.256 0.024 74.280 ;
    END
  END wd_in_A[40]
  PIN wd_in_B[40]
    DIRECTION INPUT ;
    USE SIGNAL ;
    SHAPE ABUTMENT ;
    PORT
      LAYER M4 ;
      RECT 103.336 74.256 103.360 74.280 ;
    END
  END wd_in_B[40]
  PIN wd_in_A[41]
    DIRECTION INPUT ;
    USE SIGNAL ;
    SHAPE ABUTMENT ;
    PORT
      LAYER M4 ;
      RECT 0.000 74.688 0.024 74.712 ;
    END
  END wd_in_A[41]
  PIN wd_in_B[41]
    DIRECTION INPUT ;
    USE SIGNAL ;
    SHAPE ABUTMENT ;
    PORT
      LAYER M4 ;
      RECT 103.336 74.688 103.360 74.712 ;
    END
  END wd_in_B[41]
  PIN wd_in_A[42]
    DIRECTION INPUT ;
    USE SIGNAL ;
    SHAPE ABUTMENT ;
    PORT
      LAYER M4 ;
      RECT 0.000 75.120 0.024 75.144 ;
    END
  END wd_in_A[42]
  PIN wd_in_B[42]
    DIRECTION INPUT ;
    USE SIGNAL ;
    SHAPE ABUTMENT ;
    PORT
      LAYER M4 ;
      RECT 103.336 75.120 103.360 75.144 ;
    END
  END wd_in_B[42]
  PIN wd_in_A[43]
    DIRECTION INPUT ;
    USE SIGNAL ;
    SHAPE ABUTMENT ;
    PORT
      LAYER M4 ;
      RECT 0.000 75.552 0.024 75.576 ;
    END
  END wd_in_A[43]
  PIN wd_in_B[43]
    DIRECTION INPUT ;
    USE SIGNAL ;
    SHAPE ABUTMENT ;
    PORT
      LAYER M4 ;
      RECT 103.336 75.552 103.360 75.576 ;
    END
  END wd_in_B[43]
  PIN wd_in_A[44]
    DIRECTION INPUT ;
    USE SIGNAL ;
    SHAPE ABUTMENT ;
    PORT
      LAYER M4 ;
      RECT 0.000 75.984 0.024 76.008 ;
    END
  END wd_in_A[44]
  PIN wd_in_B[44]
    DIRECTION INPUT ;
    USE SIGNAL ;
    SHAPE ABUTMENT ;
    PORT
      LAYER M4 ;
      RECT 103.336 75.984 103.360 76.008 ;
    END
  END wd_in_B[44]
  PIN wd_in_A[45]
    DIRECTION INPUT ;
    USE SIGNAL ;
    SHAPE ABUTMENT ;
    PORT
      LAYER M4 ;
      RECT 0.000 76.416 0.024 76.440 ;
    END
  END wd_in_A[45]
  PIN wd_in_B[45]
    DIRECTION INPUT ;
    USE SIGNAL ;
    SHAPE ABUTMENT ;
    PORT
      LAYER M4 ;
      RECT 103.336 76.416 103.360 76.440 ;
    END
  END wd_in_B[45]
  PIN wd_in_A[46]
    DIRECTION INPUT ;
    USE SIGNAL ;
    SHAPE ABUTMENT ;
    PORT
      LAYER M4 ;
      RECT 0.000 76.848 0.024 76.872 ;
    END
  END wd_in_A[46]
  PIN wd_in_B[46]
    DIRECTION INPUT ;
    USE SIGNAL ;
    SHAPE ABUTMENT ;
    PORT
      LAYER M4 ;
      RECT 103.336 76.848 103.360 76.872 ;
    END
  END wd_in_B[46]
  PIN wd_in_A[47]
    DIRECTION INPUT ;
    USE SIGNAL ;
    SHAPE ABUTMENT ;
    PORT
      LAYER M4 ;
      RECT 0.000 77.280 0.024 77.304 ;
    END
  END wd_in_A[47]
  PIN wd_in_B[47]
    DIRECTION INPUT ;
    USE SIGNAL ;
    SHAPE ABUTMENT ;
    PORT
      LAYER M4 ;
      RECT 103.336 77.280 103.360 77.304 ;
    END
  END wd_in_B[47]
  PIN wd_in_A[48]
    DIRECTION INPUT ;
    USE SIGNAL ;
    SHAPE ABUTMENT ;
    PORT
      LAYER M4 ;
      RECT 0.000 77.712 0.024 77.736 ;
    END
  END wd_in_A[48]
  PIN wd_in_B[48]
    DIRECTION INPUT ;
    USE SIGNAL ;
    SHAPE ABUTMENT ;
    PORT
      LAYER M4 ;
      RECT 103.336 77.712 103.360 77.736 ;
    END
  END wd_in_B[48]
  PIN wd_in_A[49]
    DIRECTION INPUT ;
    USE SIGNAL ;
    SHAPE ABUTMENT ;
    PORT
      LAYER M4 ;
      RECT 0.000 78.144 0.024 78.168 ;
    END
  END wd_in_A[49]
  PIN wd_in_B[49]
    DIRECTION INPUT ;
    USE SIGNAL ;
    SHAPE ABUTMENT ;
    PORT
      LAYER M4 ;
      RECT 103.336 78.144 103.360 78.168 ;
    END
  END wd_in_B[49]
  PIN wd_in_A[50]
    DIRECTION INPUT ;
    USE SIGNAL ;
    SHAPE ABUTMENT ;
    PORT
      LAYER M4 ;
      RECT 0.000 78.576 0.024 78.600 ;
    END
  END wd_in_A[50]
  PIN wd_in_B[50]
    DIRECTION INPUT ;
    USE SIGNAL ;
    SHAPE ABUTMENT ;
    PORT
      LAYER M4 ;
      RECT 103.336 78.576 103.360 78.600 ;
    END
  END wd_in_B[50]
  PIN wd_in_A[51]
    DIRECTION INPUT ;
    USE SIGNAL ;
    SHAPE ABUTMENT ;
    PORT
      LAYER M4 ;
      RECT 0.000 79.008 0.024 79.032 ;
    END
  END wd_in_A[51]
  PIN wd_in_B[51]
    DIRECTION INPUT ;
    USE SIGNAL ;
    SHAPE ABUTMENT ;
    PORT
      LAYER M4 ;
      RECT 103.336 79.008 103.360 79.032 ;
    END
  END wd_in_B[51]
  PIN wd_in_A[52]
    DIRECTION INPUT ;
    USE SIGNAL ;
    SHAPE ABUTMENT ;
    PORT
      LAYER M4 ;
      RECT 0.000 79.440 0.024 79.464 ;
    END
  END wd_in_A[52]
  PIN wd_in_B[52]
    DIRECTION INPUT ;
    USE SIGNAL ;
    SHAPE ABUTMENT ;
    PORT
      LAYER M4 ;
      RECT 103.336 79.440 103.360 79.464 ;
    END
  END wd_in_B[52]
  PIN wd_in_A[53]
    DIRECTION INPUT ;
    USE SIGNAL ;
    SHAPE ABUTMENT ;
    PORT
      LAYER M4 ;
      RECT 0.000 79.872 0.024 79.896 ;
    END
  END wd_in_A[53]
  PIN wd_in_B[53]
    DIRECTION INPUT ;
    USE SIGNAL ;
    SHAPE ABUTMENT ;
    PORT
      LAYER M4 ;
      RECT 103.336 79.872 103.360 79.896 ;
    END
  END wd_in_B[53]
  PIN wd_in_A[54]
    DIRECTION INPUT ;
    USE SIGNAL ;
    SHAPE ABUTMENT ;
    PORT
      LAYER M4 ;
      RECT 0.000 80.304 0.024 80.328 ;
    END
  END wd_in_A[54]
  PIN wd_in_B[54]
    DIRECTION INPUT ;
    USE SIGNAL ;
    SHAPE ABUTMENT ;
    PORT
      LAYER M4 ;
      RECT 103.336 80.304 103.360 80.328 ;
    END
  END wd_in_B[54]
  PIN wd_in_A[55]
    DIRECTION INPUT ;
    USE SIGNAL ;
    SHAPE ABUTMENT ;
    PORT
      LAYER M4 ;
      RECT 0.000 80.736 0.024 80.760 ;
    END
  END wd_in_A[55]
  PIN wd_in_B[55]
    DIRECTION INPUT ;
    USE SIGNAL ;
    SHAPE ABUTMENT ;
    PORT
      LAYER M4 ;
      RECT 103.336 80.736 103.360 80.760 ;
    END
  END wd_in_B[55]
  PIN wd_in_A[56]
    DIRECTION INPUT ;
    USE SIGNAL ;
    SHAPE ABUTMENT ;
    PORT
      LAYER M4 ;
      RECT 0.000 81.168 0.024 81.192 ;
    END
  END wd_in_A[56]
  PIN wd_in_B[56]
    DIRECTION INPUT ;
    USE SIGNAL ;
    SHAPE ABUTMENT ;
    PORT
      LAYER M4 ;
      RECT 103.336 81.168 103.360 81.192 ;
    END
  END wd_in_B[56]
  PIN wd_in_A[57]
    DIRECTION INPUT ;
    USE SIGNAL ;
    SHAPE ABUTMENT ;
    PORT
      LAYER M4 ;
      RECT 0.000 81.600 0.024 81.624 ;
    END
  END wd_in_A[57]
  PIN wd_in_B[57]
    DIRECTION INPUT ;
    USE SIGNAL ;
    SHAPE ABUTMENT ;
    PORT
      LAYER M4 ;
      RECT 103.336 81.600 103.360 81.624 ;
    END
  END wd_in_B[57]
  PIN wd_in_A[58]
    DIRECTION INPUT ;
    USE SIGNAL ;
    SHAPE ABUTMENT ;
    PORT
      LAYER M4 ;
      RECT 0.000 82.032 0.024 82.056 ;
    END
  END wd_in_A[58]
  PIN wd_in_B[58]
    DIRECTION INPUT ;
    USE SIGNAL ;
    SHAPE ABUTMENT ;
    PORT
      LAYER M4 ;
      RECT 103.336 82.032 103.360 82.056 ;
    END
  END wd_in_B[58]
  PIN wd_in_A[59]
    DIRECTION INPUT ;
    USE SIGNAL ;
    SHAPE ABUTMENT ;
    PORT
      LAYER M4 ;
      RECT 0.000 82.464 0.024 82.488 ;
    END
  END wd_in_A[59]
  PIN wd_in_B[59]
    DIRECTION INPUT ;
    USE SIGNAL ;
    SHAPE ABUTMENT ;
    PORT
      LAYER M4 ;
      RECT 103.336 82.464 103.360 82.488 ;
    END
  END wd_in_B[59]
  PIN wd_in_A[60]
    DIRECTION INPUT ;
    USE SIGNAL ;
    SHAPE ABUTMENT ;
    PORT
      LAYER M4 ;
      RECT 0.000 82.896 0.024 82.920 ;
    END
  END wd_in_A[60]
  PIN wd_in_B[60]
    DIRECTION INPUT ;
    USE SIGNAL ;
    SHAPE ABUTMENT ;
    PORT
      LAYER M4 ;
      RECT 103.336 82.896 103.360 82.920 ;
    END
  END wd_in_B[60]
  PIN wd_in_A[61]
    DIRECTION INPUT ;
    USE SIGNAL ;
    SHAPE ABUTMENT ;
    PORT
      LAYER M4 ;
      RECT 0.000 83.328 0.024 83.352 ;
    END
  END wd_in_A[61]
  PIN wd_in_B[61]
    DIRECTION INPUT ;
    USE SIGNAL ;
    SHAPE ABUTMENT ;
    PORT
      LAYER M4 ;
      RECT 103.336 83.328 103.360 83.352 ;
    END
  END wd_in_B[61]
  PIN wd_in_A[62]
    DIRECTION INPUT ;
    USE SIGNAL ;
    SHAPE ABUTMENT ;
    PORT
      LAYER M4 ;
      RECT 0.000 83.760 0.024 83.784 ;
    END
  END wd_in_A[62]
  PIN wd_in_B[62]
    DIRECTION INPUT ;
    USE SIGNAL ;
    SHAPE ABUTMENT ;
    PORT
      LAYER M4 ;
      RECT 103.336 83.760 103.360 83.784 ;
    END
  END wd_in_B[62]
  PIN wd_in_A[63]
    DIRECTION INPUT ;
    USE SIGNAL ;
    SHAPE ABUTMENT ;
    PORT
      LAYER M4 ;
      RECT 0.000 84.192 0.024 84.216 ;
    END
  END wd_in_A[63]
  PIN wd_in_B[63]
    DIRECTION INPUT ;
    USE SIGNAL ;
    SHAPE ABUTMENT ;
    PORT
      LAYER M4 ;
      RECT 103.336 84.192 103.360 84.216 ;
    END
  END wd_in_B[63]
  PIN addr_in_A[0]
    DIRECTION INPUT ;
    USE SIGNAL ;
    SHAPE ABUTMENT ;
    PORT
      LAYER M4 ;
      RECT 0.000 85.440 0.024 85.464 ;
    END
  END addr_in_A[0]
  PIN addr_in_B[0]
    DIRECTION INPUT ;
    USE SIGNAL ;
    SHAPE ABUTMENT ;
    PORT
      LAYER M4 ;
      RECT 103.336 85.440 103.360 85.464 ;
    END
  END addr_in_B[0]
  PIN addr_in_A[1]
    DIRECTION INPUT ;
    USE SIGNAL ;
    SHAPE ABUTMENT ;
    PORT
      LAYER M4 ;
      RECT 0.000 85.872 0.024 85.896 ;
    END
  END addr_in_A[1]
  PIN addr_in_B[1]
    DIRECTION INPUT ;
    USE SIGNAL ;
    SHAPE ABUTMENT ;
    PORT
      LAYER M4 ;
      RECT 103.336 85.872 103.360 85.896 ;
    END
  END addr_in_B[1]
  PIN addr_in_A[2]
    DIRECTION INPUT ;
    USE SIGNAL ;
    SHAPE ABUTMENT ;
    PORT
      LAYER M4 ;
      RECT 0.000 86.304 0.024 86.328 ;
    END
  END addr_in_A[2]
  PIN addr_in_B[2]
    DIRECTION INPUT ;
    USE SIGNAL ;
    SHAPE ABUTMENT ;
    PORT
      LAYER M4 ;
      RECT 103.336 86.304 103.360 86.328 ;
    END
  END addr_in_B[2]
  PIN addr_in_A[3]
    DIRECTION INPUT ;
    USE SIGNAL ;
    SHAPE ABUTMENT ;
    PORT
      LAYER M4 ;
      RECT 0.000 86.736 0.024 86.760 ;
    END
  END addr_in_A[3]
  PIN addr_in_B[3]
    DIRECTION INPUT ;
    USE SIGNAL ;
    SHAPE ABUTMENT ;
    PORT
      LAYER M4 ;
      RECT 103.336 86.736 103.360 86.760 ;
    END
  END addr_in_B[3]
  PIN addr_in_A[4]
    DIRECTION INPUT ;
    USE SIGNAL ;
    SHAPE ABUTMENT ;
    PORT
      LAYER M4 ;
      RECT 0.000 87.168 0.024 87.192 ;
    END
  END addr_in_A[4]
  PIN addr_in_B[4]
    DIRECTION INPUT ;
    USE SIGNAL ;
    SHAPE ABUTMENT ;
    PORT
      LAYER M4 ;
      RECT 103.336 87.168 103.360 87.192 ;
    END
  END addr_in_B[4]
  PIN addr_in_A[5]
    DIRECTION INPUT ;
    USE SIGNAL ;
    SHAPE ABUTMENT ;
    PORT
      LAYER M4 ;
      RECT 0.000 87.600 0.024 87.624 ;
    END
  END addr_in_A[5]
  PIN addr_in_B[5]
    DIRECTION INPUT ;
    USE SIGNAL ;
    SHAPE ABUTMENT ;
    PORT
      LAYER M4 ;
      RECT 103.336 87.600 103.360 87.624 ;
    END
  END addr_in_B[5]
  PIN addr_in_A[6]
    DIRECTION INPUT ;
    USE SIGNAL ;
    SHAPE ABUTMENT ;
    PORT
      LAYER M4 ;
      RECT 0.000 88.032 0.024 88.056 ;
    END
  END addr_in_A[6]
  PIN addr_in_B[6]
    DIRECTION INPUT ;
    USE SIGNAL ;
    SHAPE ABUTMENT ;
    PORT
      LAYER M4 ;
      RECT 103.336 88.032 103.360 88.056 ;
    END
  END addr_in_B[6]
  PIN addr_in_A[7]
    DIRECTION INPUT ;
    USE SIGNAL ;
    SHAPE ABUTMENT ;
    PORT
      LAYER M4 ;
      RECT 0.000 88.464 0.024 88.488 ;
    END
  END addr_in_A[7]
  PIN addr_in_B[7]
    DIRECTION INPUT ;
    USE SIGNAL ;
    SHAPE ABUTMENT ;
    PORT
      LAYER M4 ;
      RECT 103.336 88.464 103.360 88.488 ;
    END
  END addr_in_B[7]
  PIN addr_in_A[8]
    DIRECTION INPUT ;
    USE SIGNAL ;
    SHAPE ABUTMENT ;
    PORT
      LAYER M4 ;
      RECT 0.000 88.896 0.024 88.920 ;
    END
  END addr_in_A[8]
  PIN addr_in_B[8]
    DIRECTION INPUT ;
    USE SIGNAL ;
    SHAPE ABUTMENT ;
    PORT
      LAYER M4 ;
      RECT 103.336 88.896 103.360 88.920 ;
    END
  END addr_in_B[8]
  PIN addr_in_A[9]
    DIRECTION INPUT ;
    USE SIGNAL ;
    SHAPE ABUTMENT ;
    PORT
      LAYER M4 ;
      RECT 0.000 89.328 0.024 89.352 ;
    END
  END addr_in_A[9]
  PIN addr_in_B[9]
    DIRECTION INPUT ;
    USE SIGNAL ;
    SHAPE ABUTMENT ;
    PORT
      LAYER M4 ;
      RECT 103.336 89.328 103.360 89.352 ;
    END
  END addr_in_B[9]
  PIN addr_in_A[10]
    DIRECTION INPUT ;
    USE SIGNAL ;
    SHAPE ABUTMENT ;
    PORT
      LAYER M4 ;
      RECT 0.000 89.760 0.024 89.784 ;
    END
  END addr_in_A[10]
  PIN addr_in_B[10]
    DIRECTION INPUT ;
    USE SIGNAL ;
    SHAPE ABUTMENT ;
    PORT
      LAYER M4 ;
      RECT 103.336 89.760 103.360 89.784 ;
    END
  END addr_in_B[10]
  PIN we_in_A
    DIRECTION INPUT ;
    USE SIGNAL ;
    SHAPE ABUTMENT ;
    PORT
      LAYER M4 ;
      RECT 0.000 91.008 0.024 91.032 ;
    END
  END we_in_A
  PIN we_in_B
    DIRECTION INPUT ;
    USE SIGNAL ;
    SHAPE ABUTMENT ;
    PORT
      LAYER M4 ;
      RECT 103.336 91.008 103.360 91.032 ;
    END
  END we_in_B
  PIN ce_in_A
    DIRECTION INPUT ;
    USE SIGNAL ;
    SHAPE ABUTMENT ;
    PORT
      LAYER M4 ;
      RECT 0.000 91.440 0.024 91.464 ;
    END
  END ce_in_A
  PIN clk_A
    DIRECTION INPUT ;
    USE SIGNAL ;
    SHAPE ABUTMENT ;
    PORT
      LAYER M4 ;
      RECT 0.000 91.872 0.024 91.896 ;
    END
  END clk_A
  PIN ce_in_B
    DIRECTION INPUT ;
    USE SIGNAL ;
    SHAPE ABUTMENT ;
    PORT
      LAYER M4 ;
      RECT 0.000 92.304 0.024 92.328 ;
    END
  END ce_in_B
  PIN clk_B
    DIRECTION INPUT ;
    USE SIGNAL ;
    SHAPE ABUTMENT ;
    PORT
      LAYER M4 ;
      RECT 0.000 92.736 0.024 92.760 ;
    END
  END clk_B
  PIN VSS
    DIRECTION INOUT ;
    USE GROUND ;
    PORT
      LAYER M4 ;
      RECT 0.048 0.000 103.312 0.096 ;
      RECT 0.048 0.768 103.312 0.864 ;
      RECT 0.048 1.536 103.312 1.632 ;
      RECT 0.048 2.304 103.312 2.400 ;
      RECT 0.048 3.072 103.312 3.168 ;
      RECT 0.048 3.840 103.312 3.936 ;
      RECT 0.048 4.608 103.312 4.704 ;
      RECT 0.048 5.376 103.312 5.472 ;
      RECT 0.048 6.144 103.312 6.240 ;
      RECT 0.048 6.912 103.312 7.008 ;
      RECT 0.048 7.680 103.312 7.776 ;
      RECT 0.048 8.448 103.312 8.544 ;
      RECT 0.048 9.216 103.312 9.312 ;
      RECT 0.048 9.984 103.312 10.080 ;
      RECT 0.048 10.752 103.312 10.848 ;
      RECT 0.048 11.520 103.312 11.616 ;
      RECT 0.048 12.288 103.312 12.384 ;
      RECT 0.048 13.056 103.312 13.152 ;
      RECT 0.048 13.824 103.312 13.920 ;
      RECT 0.048 14.592 103.312 14.688 ;
      RECT 0.048 15.360 103.312 15.456 ;
      RECT 0.048 16.128 103.312 16.224 ;
      RECT 0.048 16.896 103.312 16.992 ;
      RECT 0.048 17.664 103.312 17.760 ;
      RECT 0.048 18.432 103.312 18.528 ;
      RECT 0.048 19.200 103.312 19.296 ;
      RECT 0.048 19.968 103.312 20.064 ;
      RECT 0.048 20.736 103.312 20.832 ;
      RECT 0.048 21.504 103.312 21.600 ;
      RECT 0.048 22.272 103.312 22.368 ;
      RECT 0.048 23.040 103.312 23.136 ;
      RECT 0.048 23.808 103.312 23.904 ;
      RECT 0.048 24.576 103.312 24.672 ;
      RECT 0.048 25.344 103.312 25.440 ;
      RECT 0.048 26.112 103.312 26.208 ;
      RECT 0.048 26.880 103.312 26.976 ;
      RECT 0.048 27.648 103.312 27.744 ;
      RECT 0.048 28.416 103.312 28.512 ;
      RECT 0.048 29.184 103.312 29.280 ;
      RECT 0.048 29.952 103.312 30.048 ;
      RECT 0.048 30.720 103.312 30.816 ;
      RECT 0.048 31.488 103.312 31.584 ;
      RECT 0.048 32.256 103.312 32.352 ;
      RECT 0.048 33.024 103.312 33.120 ;
      RECT 0.048 33.792 103.312 33.888 ;
      RECT 0.048 34.560 103.312 34.656 ;
      RECT 0.048 35.328 103.312 35.424 ;
      RECT 0.048 36.096 103.312 36.192 ;
      RECT 0.048 36.864 103.312 36.960 ;
      RECT 0.048 37.632 103.312 37.728 ;
      RECT 0.048 38.400 103.312 38.496 ;
      RECT 0.048 39.168 103.312 39.264 ;
      RECT 0.048 39.936 103.312 40.032 ;
      RECT 0.048 40.704 103.312 40.800 ;
      RECT 0.048 41.472 103.312 41.568 ;
      RECT 0.048 42.240 103.312 42.336 ;
      RECT 0.048 43.008 103.312 43.104 ;
      RECT 0.048 43.776 103.312 43.872 ;
      RECT 0.048 44.544 103.312 44.640 ;
      RECT 0.048 45.312 103.312 45.408 ;
      RECT 0.048 46.080 103.312 46.176 ;
      RECT 0.048 46.848 103.312 46.944 ;
      RECT 0.048 47.616 103.312 47.712 ;
      RECT 0.048 48.384 103.312 48.480 ;
      RECT 0.048 49.152 103.312 49.248 ;
      RECT 0.048 49.920 103.312 50.016 ;
      RECT 0.048 50.688 103.312 50.784 ;
      RECT 0.048 51.456 103.312 51.552 ;
      RECT 0.048 52.224 103.312 52.320 ;
      RECT 0.048 52.992 103.312 53.088 ;
      RECT 0.048 53.760 103.312 53.856 ;
      RECT 0.048 54.528 103.312 54.624 ;
      RECT 0.048 55.296 103.312 55.392 ;
      RECT 0.048 56.064 103.312 56.160 ;
      RECT 0.048 56.832 103.312 56.928 ;
      RECT 0.048 57.600 103.312 57.696 ;
      RECT 0.048 58.368 103.312 58.464 ;
      RECT 0.048 59.136 103.312 59.232 ;
      RECT 0.048 59.904 103.312 60.000 ;
      RECT 0.048 60.672 103.312 60.768 ;
      RECT 0.048 61.440 103.312 61.536 ;
      RECT 0.048 62.208 103.312 62.304 ;
      RECT 0.048 62.976 103.312 63.072 ;
      RECT 0.048 63.744 103.312 63.840 ;
      RECT 0.048 64.512 103.312 64.608 ;
      RECT 0.048 65.280 103.312 65.376 ;
      RECT 0.048 66.048 103.312 66.144 ;
      RECT 0.048 66.816 103.312 66.912 ;
      RECT 0.048 67.584 103.312 67.680 ;
      RECT 0.048 68.352 103.312 68.448 ;
      RECT 0.048 69.120 103.312 69.216 ;
      RECT 0.048 69.888 103.312 69.984 ;
      RECT 0.048 70.656 103.312 70.752 ;
      RECT 0.048 71.424 103.312 71.520 ;
      RECT 0.048 72.192 103.312 72.288 ;
      RECT 0.048 72.960 103.312 73.056 ;
      RECT 0.048 73.728 103.312 73.824 ;
      RECT 0.048 74.496 103.312 74.592 ;
      RECT 0.048 75.264 103.312 75.360 ;
      RECT 0.048 76.032 103.312 76.128 ;
      RECT 0.048 76.800 103.312 76.896 ;
      RECT 0.048 77.568 103.312 77.664 ;
      RECT 0.048 78.336 103.312 78.432 ;
      RECT 0.048 79.104 103.312 79.200 ;
      RECT 0.048 79.872 103.312 79.968 ;
      RECT 0.048 80.640 103.312 80.736 ;
      RECT 0.048 81.408 103.312 81.504 ;
      RECT 0.048 82.176 103.312 82.272 ;
      RECT 0.048 82.944 103.312 83.040 ;
      RECT 0.048 83.712 103.312 83.808 ;
      RECT 0.048 84.480 103.312 84.576 ;
      RECT 0.048 85.248 103.312 85.344 ;
      RECT 0.048 86.016 103.312 86.112 ;
      RECT 0.048 86.784 103.312 86.880 ;
      RECT 0.048 87.552 103.312 87.648 ;
      RECT 0.048 88.320 103.312 88.416 ;
      RECT 0.048 89.088 103.312 89.184 ;
      RECT 0.048 89.856 103.312 89.952 ;
      RECT 0.048 90.624 103.312 90.720 ;
      RECT 0.048 91.392 103.312 91.488 ;
      RECT 0.048 92.160 103.312 92.256 ;
    END
  END VSS
  PIN VDD
    DIRECTION INOUT ;
    USE POWER ;
    PORT
      LAYER M4 ;
      RECT 0.048 0.384 103.312 0.480 ;
      RECT 0.048 1.152 103.312 1.248 ;
      RECT 0.048 1.920 103.312 2.016 ;
      RECT 0.048 2.688 103.312 2.784 ;
      RECT 0.048 3.456 103.312 3.552 ;
      RECT 0.048 4.224 103.312 4.320 ;
      RECT 0.048 4.992 103.312 5.088 ;
      RECT 0.048 5.760 103.312 5.856 ;
      RECT 0.048 6.528 103.312 6.624 ;
      RECT 0.048 7.296 103.312 7.392 ;
      RECT 0.048 8.064 103.312 8.160 ;
      RECT 0.048 8.832 103.312 8.928 ;
      RECT 0.048 9.600 103.312 9.696 ;
      RECT 0.048 10.368 103.312 10.464 ;
      RECT 0.048 11.136 103.312 11.232 ;
      RECT 0.048 11.904 103.312 12.000 ;
      RECT 0.048 12.672 103.312 12.768 ;
      RECT 0.048 13.440 103.312 13.536 ;
      RECT 0.048 14.208 103.312 14.304 ;
      RECT 0.048 14.976 103.312 15.072 ;
      RECT 0.048 15.744 103.312 15.840 ;
      RECT 0.048 16.512 103.312 16.608 ;
      RECT 0.048 17.280 103.312 17.376 ;
      RECT 0.048 18.048 103.312 18.144 ;
      RECT 0.048 18.816 103.312 18.912 ;
      RECT 0.048 19.584 103.312 19.680 ;
      RECT 0.048 20.352 103.312 20.448 ;
      RECT 0.048 21.120 103.312 21.216 ;
      RECT 0.048 21.888 103.312 21.984 ;
      RECT 0.048 22.656 103.312 22.752 ;
      RECT 0.048 23.424 103.312 23.520 ;
      RECT 0.048 24.192 103.312 24.288 ;
      RECT 0.048 24.960 103.312 25.056 ;
      RECT 0.048 25.728 103.312 25.824 ;
      RECT 0.048 26.496 103.312 26.592 ;
      RECT 0.048 27.264 103.312 27.360 ;
      RECT 0.048 28.032 103.312 28.128 ;
      RECT 0.048 28.800 103.312 28.896 ;
      RECT 0.048 29.568 103.312 29.664 ;
      RECT 0.048 30.336 103.312 30.432 ;
      RECT 0.048 31.104 103.312 31.200 ;
      RECT 0.048 31.872 103.312 31.968 ;
      RECT 0.048 32.640 103.312 32.736 ;
      RECT 0.048 33.408 103.312 33.504 ;
      RECT 0.048 34.176 103.312 34.272 ;
      RECT 0.048 34.944 103.312 35.040 ;
      RECT 0.048 35.712 103.312 35.808 ;
      RECT 0.048 36.480 103.312 36.576 ;
      RECT 0.048 37.248 103.312 37.344 ;
      RECT 0.048 38.016 103.312 38.112 ;
      RECT 0.048 38.784 103.312 38.880 ;
      RECT 0.048 39.552 103.312 39.648 ;
      RECT 0.048 40.320 103.312 40.416 ;
      RECT 0.048 41.088 103.312 41.184 ;
      RECT 0.048 41.856 103.312 41.952 ;
      RECT 0.048 42.624 103.312 42.720 ;
      RECT 0.048 43.392 103.312 43.488 ;
      RECT 0.048 44.160 103.312 44.256 ;
      RECT 0.048 44.928 103.312 45.024 ;
      RECT 0.048 45.696 103.312 45.792 ;
      RECT 0.048 46.464 103.312 46.560 ;
      RECT 0.048 47.232 103.312 47.328 ;
      RECT 0.048 48.000 103.312 48.096 ;
      RECT 0.048 48.768 103.312 48.864 ;
      RECT 0.048 49.536 103.312 49.632 ;
      RECT 0.048 50.304 103.312 50.400 ;
      RECT 0.048 51.072 103.312 51.168 ;
      RECT 0.048 51.840 103.312 51.936 ;
      RECT 0.048 52.608 103.312 52.704 ;
      RECT 0.048 53.376 103.312 53.472 ;
      RECT 0.048 54.144 103.312 54.240 ;
      RECT 0.048 54.912 103.312 55.008 ;
      RECT 0.048 55.680 103.312 55.776 ;
      RECT 0.048 56.448 103.312 56.544 ;
      RECT 0.048 57.216 103.312 57.312 ;
      RECT 0.048 57.984 103.312 58.080 ;
      RECT 0.048 58.752 103.312 58.848 ;
      RECT 0.048 59.520 103.312 59.616 ;
      RECT 0.048 60.288 103.312 60.384 ;
      RECT 0.048 61.056 103.312 61.152 ;
      RECT 0.048 61.824 103.312 61.920 ;
      RECT 0.048 62.592 103.312 62.688 ;
      RECT 0.048 63.360 103.312 63.456 ;
      RECT 0.048 64.128 103.312 64.224 ;
      RECT 0.048 64.896 103.312 64.992 ;
      RECT 0.048 65.664 103.312 65.760 ;
      RECT 0.048 66.432 103.312 66.528 ;
      RECT 0.048 67.200 103.312 67.296 ;
      RECT 0.048 67.968 103.312 68.064 ;
      RECT 0.048 68.736 103.312 68.832 ;
      RECT 0.048 69.504 103.312 69.600 ;
      RECT 0.048 70.272 103.312 70.368 ;
      RECT 0.048 71.040 103.312 71.136 ;
      RECT 0.048 71.808 103.312 71.904 ;
      RECT 0.048 72.576 103.312 72.672 ;
      RECT 0.048 73.344 103.312 73.440 ;
      RECT 0.048 74.112 103.312 74.208 ;
      RECT 0.048 74.880 103.312 74.976 ;
      RECT 0.048 75.648 103.312 75.744 ;
      RECT 0.048 76.416 103.312 76.512 ;
      RECT 0.048 77.184 103.312 77.280 ;
      RECT 0.048 77.952 103.312 78.048 ;
      RECT 0.048 78.720 103.312 78.816 ;
      RECT 0.048 79.488 103.312 79.584 ;
      RECT 0.048 80.256 103.312 80.352 ;
      RECT 0.048 81.024 103.312 81.120 ;
      RECT 0.048 81.792 103.312 81.888 ;
      RECT 0.048 82.560 103.312 82.656 ;
      RECT 0.048 83.328 103.312 83.424 ;
      RECT 0.048 84.096 103.312 84.192 ;
      RECT 0.048 84.864 103.312 84.960 ;
      RECT 0.048 85.632 103.312 85.728 ;
      RECT 0.048 86.400 103.312 86.496 ;
      RECT 0.048 87.168 103.312 87.264 ;
      RECT 0.048 87.936 103.312 88.032 ;
      RECT 0.048 88.704 103.312 88.800 ;
      RECT 0.048 89.472 103.312 89.568 ;
      RECT 0.048 90.240 103.312 90.336 ;
      RECT 0.048 91.008 103.312 91.104 ;
      RECT 0.048 91.776 103.312 91.872 ;
    END
  END VDD
  OBS
    LAYER M1 ;
    RECT 0 0 103.360 92.400 ;
    LAYER M2 ;
    RECT 0 0 103.360 92.400 ;
    LAYER M3 ;
    RECT 0 0 103.360 92.400 ;
    LAYER M4 ;
    RECT 0 0 103.360 92.400 ;
  END
END fakeram7_tdp_2048x64

END LIBRARY
